VERSION 5.8 ;
BUSBITCHARS "[]" ;
DIVIDERCHAR "/" ;
UNITS
    DATABASE MICRONS 1000 ;
END UNITS

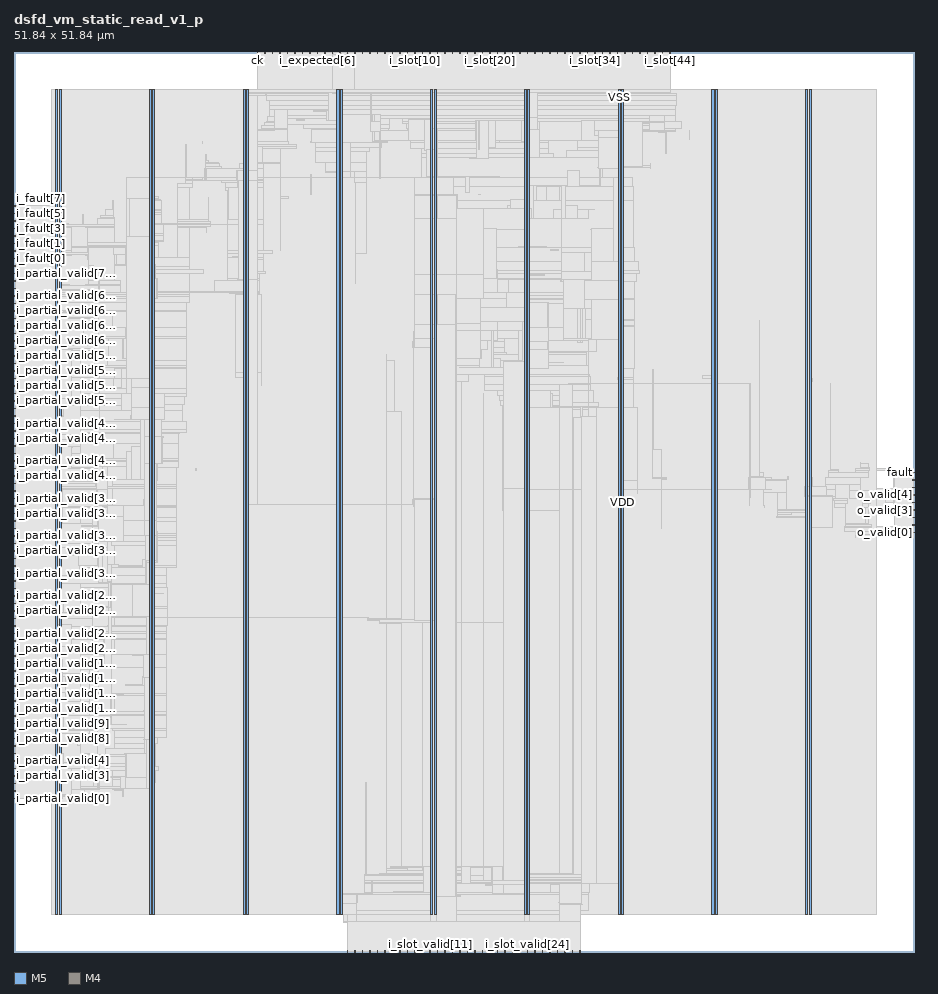
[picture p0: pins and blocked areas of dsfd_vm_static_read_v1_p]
MACRO dsfd_vm_static_read_v1_p
  FOREIGN dsfd_vm_static_read_v1_p 0 0 ;
  CLASS BLOCK ;
  SIZE 51.84 BY 51.84 ;
  PIN ck
    DIRECTION INPUT ;
    USE SIGNAL ;
    PORT
      LAYER M5 ;
        RECT  14.016 51.756 14.04 51.84 ;
    END
  END ck
  PIN fault
    DIRECTION OUTPUT ;
    USE SIGNAL ;
    PORT
      LAYER M4 ;
        RECT  51.756 27.6 51.84 27.624 ;
    END
  END fault
  PIN i_expected[0]
    DIRECTION INPUT ;
    USE SIGNAL ;
    PORT
      LAYER M5 ;
        RECT  14.88 51.756 14.904 51.84 ;
    END
  END i_expected[0]
  PIN i_expected[1]
    DIRECTION INPUT ;
    USE SIGNAL ;
    PORT
      LAYER M5 ;
        RECT  15.312 51.756 15.336 51.84 ;
    END
  END i_expected[1]
  PIN i_expected[2]
    DIRECTION INPUT ;
    USE SIGNAL ;
    PORT
      LAYER M5 ;
        RECT  15.744 51.756 15.768 51.84 ;
    END
  END i_expected[2]
  PIN i_expected[3]
    DIRECTION INPUT ;
    USE SIGNAL ;
    PORT
      LAYER M5 ;
        RECT  16.176 51.756 16.2 51.84 ;
    END
  END i_expected[3]
  PIN i_expected[4]
    DIRECTION INPUT ;
    USE SIGNAL ;
    PORT
      LAYER M5 ;
        RECT  16.608 51.756 16.632 51.84 ;
    END
  END i_expected[4]
  PIN i_expected[5]
    DIRECTION INPUT ;
    USE SIGNAL ;
    PORT
      LAYER M5 ;
        RECT  17.04 51.756 17.064 51.84 ;
    END
  END i_expected[5]
  PIN i_expected[6]
    DIRECTION INPUT ;
    USE SIGNAL ;
    PORT
      LAYER M5 ;
        RECT  17.472 51.756 17.496 51.84 ;
    END
  END i_expected[6]
  PIN i_expected[7]
    DIRECTION INPUT ;
    USE SIGNAL ;
    PORT
      LAYER M5 ;
        RECT  17.904 51.756 17.928 51.84 ;
    END
  END i_expected[7]
  PIN i_expected[8]
    DIRECTION INPUT ;
    USE SIGNAL ;
    PORT
      LAYER M5 ;
        RECT  18.336 51.756 18.36 51.84 ;
    END
  END i_expected[8]
  PIN i_fault[0]
    DIRECTION INPUT ;
    USE SIGNAL ;
    PORT
      LAYER M4 ;
        RECT  0 39.936 0.084 39.96 ;
    END
  END i_fault[0]
  PIN i_fault[1]
    DIRECTION INPUT ;
    USE SIGNAL ;
    PORT
      LAYER M4 ;
        RECT  0 40.368 0.084 40.392 ;
    END
  END i_fault[1]
  PIN i_fault[2]
    DIRECTION INPUT ;
    USE SIGNAL ;
    PORT
      LAYER M4 ;
        RECT  0 40.8 0.084 40.824 ;
    END
  END i_fault[2]
  PIN i_fault[3]
    DIRECTION INPUT ;
    USE SIGNAL ;
    PORT
      LAYER M4 ;
        RECT  0 41.232 0.084 41.256 ;
    END
  END i_fault[3]
  PIN i_fault[4]
    DIRECTION INPUT ;
    USE SIGNAL ;
    PORT
      LAYER M4 ;
        RECT  0 41.664 0.084 41.688 ;
    END
  END i_fault[4]
  PIN i_fault[5]
    DIRECTION INPUT ;
    USE SIGNAL ;
    PORT
      LAYER M4 ;
        RECT  0 42.096 0.084 42.12 ;
    END
  END i_fault[5]
  PIN i_fault[6]
    DIRECTION INPUT ;
    USE SIGNAL ;
    PORT
      LAYER M4 ;
        RECT  0 42.528 0.084 42.552 ;
    END
  END i_fault[6]
  PIN i_fault[7]
    DIRECTION INPUT ;
    USE SIGNAL ;
    PORT
      LAYER M4 ;
        RECT  0 42.96 0.084 42.984 ;
    END
  END i_fault[7]
  PIN i_partial_valid[0]
    DIRECTION INPUT ;
    USE SIGNAL ;
    PORT
      LAYER M4 ;
        RECT  0 8.832 0.084 8.856 ;
    END
  END i_partial_valid[0]
  PIN i_partial_valid[10]
    DIRECTION INPUT ;
    USE SIGNAL ;
    PORT
      LAYER M4 ;
        RECT  0 13.152 0.084 13.176 ;
    END
  END i_partial_valid[10]
  PIN i_partial_valid[11]
    DIRECTION INPUT ;
    USE SIGNAL ;
    PORT
      LAYER M4 ;
        RECT  0 13.584 0.084 13.608 ;
    END
  END i_partial_valid[11]
  PIN i_partial_valid[12]
    DIRECTION INPUT ;
    USE SIGNAL ;
    PORT
      LAYER M4 ;
        RECT  0 14.016 0.084 14.04 ;
    END
  END i_partial_valid[12]
  PIN i_partial_valid[13]
    DIRECTION INPUT ;
    USE SIGNAL ;
    PORT
      LAYER M4 ;
        RECT  0 14.448 0.084 14.472 ;
    END
  END i_partial_valid[13]
  PIN i_partial_valid[14]
    DIRECTION INPUT ;
    USE SIGNAL ;
    PORT
      LAYER M4 ;
        RECT  0 14.88 0.084 14.904 ;
    END
  END i_partial_valid[14]
  PIN i_partial_valid[15]
    DIRECTION INPUT ;
    USE SIGNAL ;
    PORT
      LAYER M4 ;
        RECT  0 15.312 0.084 15.336 ;
    END
  END i_partial_valid[15]
  PIN i_partial_valid[16]
    DIRECTION INPUT ;
    USE SIGNAL ;
    PORT
      LAYER M4 ;
        RECT  0 15.744 0.084 15.768 ;
    END
  END i_partial_valid[16]
  PIN i_partial_valid[17]
    DIRECTION INPUT ;
    USE SIGNAL ;
    PORT
      LAYER M4 ;
        RECT  0 16.176 0.084 16.2 ;
    END
  END i_partial_valid[17]
  PIN i_partial_valid[18]
    DIRECTION INPUT ;
    USE SIGNAL ;
    PORT
      LAYER M4 ;
        RECT  0 16.608 0.084 16.632 ;
    END
  END i_partial_valid[18]
  PIN i_partial_valid[19]
    DIRECTION INPUT ;
    USE SIGNAL ;
    PORT
      LAYER M4 ;
        RECT  0 17.04 0.084 17.064 ;
    END
  END i_partial_valid[19]
  PIN i_partial_valid[1]
    DIRECTION INPUT ;
    USE SIGNAL ;
    PORT
      LAYER M4 ;
        RECT  0 9.264 0.084 9.288 ;
    END
  END i_partial_valid[1]
  PIN i_partial_valid[20]
    DIRECTION INPUT ;
    USE SIGNAL ;
    PORT
      LAYER M4 ;
        RECT  0 17.472 0.084 17.496 ;
    END
  END i_partial_valid[20]
  PIN i_partial_valid[21]
    DIRECTION INPUT ;
    USE SIGNAL ;
    PORT
      LAYER M4 ;
        RECT  0 17.904 0.084 17.928 ;
    END
  END i_partial_valid[21]
  PIN i_partial_valid[22]
    DIRECTION INPUT ;
    USE SIGNAL ;
    PORT
      LAYER M4 ;
        RECT  0 18.336 0.084 18.36 ;
    END
  END i_partial_valid[22]
  PIN i_partial_valid[23]
    DIRECTION INPUT ;
    USE SIGNAL ;
    PORT
      LAYER M4 ;
        RECT  0 18.768 0.084 18.792 ;
    END
  END i_partial_valid[23]
  PIN i_partial_valid[24]
    DIRECTION INPUT ;
    USE SIGNAL ;
    PORT
      LAYER M4 ;
        RECT  0 19.2 0.084 19.224 ;
    END
  END i_partial_valid[24]
  PIN i_partial_valid[25]
    DIRECTION INPUT ;
    USE SIGNAL ;
    PORT
      LAYER M4 ;
        RECT  0 19.632 0.084 19.656 ;
    END
  END i_partial_valid[25]
  PIN i_partial_valid[26]
    DIRECTION INPUT ;
    USE SIGNAL ;
    PORT
      LAYER M4 ;
        RECT  0 20.064 0.084 20.088 ;
    END
  END i_partial_valid[26]
  PIN i_partial_valid[27]
    DIRECTION INPUT ;
    USE SIGNAL ;
    PORT
      LAYER M4 ;
        RECT  0 20.496 0.084 20.52 ;
    END
  END i_partial_valid[27]
  PIN i_partial_valid[28]
    DIRECTION INPUT ;
    USE SIGNAL ;
    PORT
      LAYER M4 ;
        RECT  0 20.928 0.084 20.952 ;
    END
  END i_partial_valid[28]
  PIN i_partial_valid[29]
    DIRECTION INPUT ;
    USE SIGNAL ;
    PORT
      LAYER M4 ;
        RECT  0 21.36 0.084 21.384 ;
    END
  END i_partial_valid[29]
  PIN i_partial_valid[2]
    DIRECTION INPUT ;
    USE SIGNAL ;
    PORT
      LAYER M4 ;
        RECT  0 9.696 0.084 9.72 ;
    END
  END i_partial_valid[2]
  PIN i_partial_valid[30]
    DIRECTION INPUT ;
    USE SIGNAL ;
    PORT
      LAYER M4 ;
        RECT  0 21.792 0.084 21.816 ;
    END
  END i_partial_valid[30]
  PIN i_partial_valid[31]
    DIRECTION INPUT ;
    USE SIGNAL ;
    PORT
      LAYER M4 ;
        RECT  0 22.224 0.084 22.248 ;
    END
  END i_partial_valid[31]
  PIN i_partial_valid[32]
    DIRECTION INPUT ;
    USE SIGNAL ;
    PORT
      LAYER M4 ;
        RECT  0 22.656 0.084 22.68 ;
    END
  END i_partial_valid[32]
  PIN i_partial_valid[33]
    DIRECTION INPUT ;
    USE SIGNAL ;
    PORT
      LAYER M4 ;
        RECT  0 23.088 0.084 23.112 ;
    END
  END i_partial_valid[33]
  PIN i_partial_valid[34]
    DIRECTION INPUT ;
    USE SIGNAL ;
    PORT
      LAYER M4 ;
        RECT  0 23.52 0.084 23.544 ;
    END
  END i_partial_valid[34]
  PIN i_partial_valid[35]
    DIRECTION INPUT ;
    USE SIGNAL ;
    PORT
      LAYER M4 ;
        RECT  0 23.952 0.084 23.976 ;
    END
  END i_partial_valid[35]
  PIN i_partial_valid[36]
    DIRECTION INPUT ;
    USE SIGNAL ;
    PORT
      LAYER M4 ;
        RECT  0 24.384 0.084 24.408 ;
    END
  END i_partial_valid[36]
  PIN i_partial_valid[37]
    DIRECTION INPUT ;
    USE SIGNAL ;
    PORT
      LAYER M4 ;
        RECT  0 24.816 0.084 24.84 ;
    END
  END i_partial_valid[37]
  PIN i_partial_valid[38]
    DIRECTION INPUT ;
    USE SIGNAL ;
    PORT
      LAYER M4 ;
        RECT  0 25.248 0.084 25.272 ;
    END
  END i_partial_valid[38]
  PIN i_partial_valid[39]
    DIRECTION INPUT ;
    USE SIGNAL ;
    PORT
      LAYER M4 ;
        RECT  0 25.68 0.084 25.704 ;
    END
  END i_partial_valid[39]
  PIN i_partial_valid[3]
    DIRECTION INPUT ;
    USE SIGNAL ;
    PORT
      LAYER M4 ;
        RECT  0 10.128 0.084 10.152 ;
    END
  END i_partial_valid[3]
  PIN i_partial_valid[40]
    DIRECTION INPUT ;
    USE SIGNAL ;
    PORT
      LAYER M4 ;
        RECT  0 26.112 0.084 26.136 ;
    END
  END i_partial_valid[40]
  PIN i_partial_valid[41]
    DIRECTION INPUT ;
    USE SIGNAL ;
    PORT
      LAYER M4 ;
        RECT  0 26.544 0.084 26.568 ;
    END
  END i_partial_valid[41]
  PIN i_partial_valid[42]
    DIRECTION INPUT ;
    USE SIGNAL ;
    PORT
      LAYER M4 ;
        RECT  0 26.976 0.084 27 ;
    END
  END i_partial_valid[42]
  PIN i_partial_valid[43]
    DIRECTION INPUT ;
    USE SIGNAL ;
    PORT
      LAYER M4 ;
        RECT  0 27.408 0.084 27.432 ;
    END
  END i_partial_valid[43]
  PIN i_partial_valid[44]
    DIRECTION INPUT ;
    USE SIGNAL ;
    PORT
      LAYER M4 ;
        RECT  0 27.84 0.084 27.864 ;
    END
  END i_partial_valid[44]
  PIN i_partial_valid[45]
    DIRECTION INPUT ;
    USE SIGNAL ;
    PORT
      LAYER M4 ;
        RECT  0 28.272 0.084 28.296 ;
    END
  END i_partial_valid[45]
  PIN i_partial_valid[46]
    DIRECTION INPUT ;
    USE SIGNAL ;
    PORT
      LAYER M4 ;
        RECT  0 28.704 0.084 28.728 ;
    END
  END i_partial_valid[46]
  PIN i_partial_valid[47]
    DIRECTION INPUT ;
    USE SIGNAL ;
    PORT
      LAYER M4 ;
        RECT  0 29.136 0.084 29.16 ;
    END
  END i_partial_valid[47]
  PIN i_partial_valid[48]
    DIRECTION INPUT ;
    USE SIGNAL ;
    PORT
      LAYER M4 ;
        RECT  0 29.568 0.084 29.592 ;
    END
  END i_partial_valid[48]
  PIN i_partial_valid[49]
    DIRECTION INPUT ;
    USE SIGNAL ;
    PORT
      LAYER M4 ;
        RECT  0 30 0.084 30.024 ;
    END
  END i_partial_valid[49]
  PIN i_partial_valid[4]
    DIRECTION INPUT ;
    USE SIGNAL ;
    PORT
      LAYER M4 ;
        RECT  0 10.56 0.084 10.584 ;
    END
  END i_partial_valid[4]
  PIN i_partial_valid[50]
    DIRECTION INPUT ;
    USE SIGNAL ;
    PORT
      LAYER M4 ;
        RECT  0 30.432 0.084 30.456 ;
    END
  END i_partial_valid[50]
  PIN i_partial_valid[51]
    DIRECTION INPUT ;
    USE SIGNAL ;
    PORT
      LAYER M4 ;
        RECT  0 30.864 0.084 30.888 ;
    END
  END i_partial_valid[51]
  PIN i_partial_valid[52]
    DIRECTION INPUT ;
    USE SIGNAL ;
    PORT
      LAYER M4 ;
        RECT  0 31.296 0.084 31.32 ;
    END
  END i_partial_valid[52]
  PIN i_partial_valid[53]
    DIRECTION INPUT ;
    USE SIGNAL ;
    PORT
      LAYER M4 ;
        RECT  0 31.728 0.084 31.752 ;
    END
  END i_partial_valid[53]
  PIN i_partial_valid[54]
    DIRECTION INPUT ;
    USE SIGNAL ;
    PORT
      LAYER M4 ;
        RECT  0 32.16 0.084 32.184 ;
    END
  END i_partial_valid[54]
  PIN i_partial_valid[55]
    DIRECTION INPUT ;
    USE SIGNAL ;
    PORT
      LAYER M4 ;
        RECT  0 32.592 0.084 32.616 ;
    END
  END i_partial_valid[55]
  PIN i_partial_valid[56]
    DIRECTION INPUT ;
    USE SIGNAL ;
    PORT
      LAYER M4 ;
        RECT  0 33.024 0.084 33.048 ;
    END
  END i_partial_valid[56]
  PIN i_partial_valid[57]
    DIRECTION INPUT ;
    USE SIGNAL ;
    PORT
      LAYER M4 ;
        RECT  0 33.456 0.084 33.48 ;
    END
  END i_partial_valid[57]
  PIN i_partial_valid[58]
    DIRECTION INPUT ;
    USE SIGNAL ;
    PORT
      LAYER M4 ;
        RECT  0 33.888 0.084 33.912 ;
    END
  END i_partial_valid[58]
  PIN i_partial_valid[59]
    DIRECTION INPUT ;
    USE SIGNAL ;
    PORT
      LAYER M4 ;
        RECT  0 34.32 0.084 34.344 ;
    END
  END i_partial_valid[59]
  PIN i_partial_valid[5]
    DIRECTION INPUT ;
    USE SIGNAL ;
    PORT
      LAYER M4 ;
        RECT  0 10.992 0.084 11.016 ;
    END
  END i_partial_valid[5]
  PIN i_partial_valid[60]
    DIRECTION INPUT ;
    USE SIGNAL ;
    PORT
      LAYER M4 ;
        RECT  0 34.752 0.084 34.776 ;
    END
  END i_partial_valid[60]
  PIN i_partial_valid[61]
    DIRECTION INPUT ;
    USE SIGNAL ;
    PORT
      LAYER M4 ;
        RECT  0 35.184 0.084 35.208 ;
    END
  END i_partial_valid[61]
  PIN i_partial_valid[62]
    DIRECTION INPUT ;
    USE SIGNAL ;
    PORT
      LAYER M4 ;
        RECT  0 35.616 0.084 35.64 ;
    END
  END i_partial_valid[62]
  PIN i_partial_valid[63]
    DIRECTION INPUT ;
    USE SIGNAL ;
    PORT
      LAYER M4 ;
        RECT  0 36.048 0.084 36.072 ;
    END
  END i_partial_valid[63]
  PIN i_partial_valid[64]
    DIRECTION INPUT ;
    USE SIGNAL ;
    PORT
      LAYER M4 ;
        RECT  0 36.48 0.084 36.504 ;
    END
  END i_partial_valid[64]
  PIN i_partial_valid[65]
    DIRECTION INPUT ;
    USE SIGNAL ;
    PORT
      LAYER M4 ;
        RECT  0 36.912 0.084 36.936 ;
    END
  END i_partial_valid[65]
  PIN i_partial_valid[66]
    DIRECTION INPUT ;
    USE SIGNAL ;
    PORT
      LAYER M4 ;
        RECT  0 37.344 0.084 37.368 ;
    END
  END i_partial_valid[66]
  PIN i_partial_valid[67]
    DIRECTION INPUT ;
    USE SIGNAL ;
    PORT
      LAYER M4 ;
        RECT  0 37.776 0.084 37.8 ;
    END
  END i_partial_valid[67]
  PIN i_partial_valid[68]
    DIRECTION INPUT ;
    USE SIGNAL ;
    PORT
      LAYER M4 ;
        RECT  0 38.208 0.084 38.232 ;
    END
  END i_partial_valid[68]
  PIN i_partial_valid[69]
    DIRECTION INPUT ;
    USE SIGNAL ;
    PORT
      LAYER M4 ;
        RECT  0 38.64 0.084 38.664 ;
    END
  END i_partial_valid[69]
  PIN i_partial_valid[6]
    DIRECTION INPUT ;
    USE SIGNAL ;
    PORT
      LAYER M4 ;
        RECT  0 11.424 0.084 11.448 ;
    END
  END i_partial_valid[6]
  PIN i_partial_valid[70]
    DIRECTION INPUT ;
    USE SIGNAL ;
    PORT
      LAYER M4 ;
        RECT  0 39.072 0.084 39.096 ;
    END
  END i_partial_valid[70]
  PIN i_partial_valid[71]
    DIRECTION INPUT ;
    USE SIGNAL ;
    PORT
      LAYER M4 ;
        RECT  0 39.504 0.084 39.528 ;
    END
  END i_partial_valid[71]
  PIN i_partial_valid[7]
    DIRECTION INPUT ;
    USE SIGNAL ;
    PORT
      LAYER M4 ;
        RECT  0 11.856 0.084 11.88 ;
    END
  END i_partial_valid[7]
  PIN i_partial_valid[8]
    DIRECTION INPUT ;
    USE SIGNAL ;
    PORT
      LAYER M4 ;
        RECT  0 12.288 0.084 12.312 ;
    END
  END i_partial_valid[8]
  PIN i_partial_valid[9]
    DIRECTION INPUT ;
    USE SIGNAL ;
    PORT
      LAYER M4 ;
        RECT  0 12.72 0.084 12.744 ;
    END
  END i_partial_valid[9]
  PIN i_slot[0]
    DIRECTION INPUT ;
    USE SIGNAL ;
    PORT
      LAYER M5 ;
        RECT  18.768 51.756 18.792 51.84 ;
    END
  END i_slot[0]
  PIN i_slot[10]
    DIRECTION INPUT ;
    USE SIGNAL ;
    PORT
      LAYER M5 ;
        RECT  23.088 51.756 23.112 51.84 ;
    END
  END i_slot[10]
  PIN i_slot[11]
    DIRECTION INPUT ;
    USE SIGNAL ;
    PORT
      LAYER M5 ;
        RECT  23.52 51.756 23.544 51.84 ;
    END
  END i_slot[11]
  PIN i_slot[12]
    DIRECTION INPUT ;
    USE SIGNAL ;
    PORT
      LAYER M5 ;
        RECT  23.952 51.756 23.976 51.84 ;
    END
  END i_slot[12]
  PIN i_slot[13]
    DIRECTION INPUT ;
    USE SIGNAL ;
    PORT
      LAYER M5 ;
        RECT  24.384 51.756 24.408 51.84 ;
    END
  END i_slot[13]
  PIN i_slot[14]
    DIRECTION INPUT ;
    USE SIGNAL ;
    PORT
      LAYER M5 ;
        RECT  24.816 51.756 24.84 51.84 ;
    END
  END i_slot[14]
  PIN i_slot[15]
    DIRECTION INPUT ;
    USE SIGNAL ;
    PORT
      LAYER M5 ;
        RECT  25.248 51.756 25.272 51.84 ;
    END
  END i_slot[15]
  PIN i_slot[16]
    DIRECTION INPUT ;
    USE SIGNAL ;
    PORT
      LAYER M5 ;
        RECT  25.68 51.756 25.704 51.84 ;
    END
  END i_slot[16]
  PIN i_slot[17]
    DIRECTION INPUT ;
    USE SIGNAL ;
    PORT
      LAYER M5 ;
        RECT  26.112 51.756 26.136 51.84 ;
    END
  END i_slot[17]
  PIN i_slot[18]
    DIRECTION INPUT ;
    USE SIGNAL ;
    PORT
      LAYER M5 ;
        RECT  26.544 51.756 26.568 51.84 ;
    END
  END i_slot[18]
  PIN i_slot[19]
    DIRECTION INPUT ;
    USE SIGNAL ;
    PORT
      LAYER M5 ;
        RECT  26.976 51.756 27 51.84 ;
    END
  END i_slot[19]
  PIN i_slot[1]
    DIRECTION INPUT ;
    USE SIGNAL ;
    PORT
      LAYER M5 ;
        RECT  19.2 51.756 19.224 51.84 ;
    END
  END i_slot[1]
  PIN i_slot[20]
    DIRECTION INPUT ;
    USE SIGNAL ;
    PORT
      LAYER M5 ;
        RECT  27.408 51.756 27.432 51.84 ;
    END
  END i_slot[20]
  PIN i_slot[21]
    DIRECTION INPUT ;
    USE SIGNAL ;
    PORT
      LAYER M5 ;
        RECT  27.84 51.756 27.864 51.84 ;
    END
  END i_slot[21]
  PIN i_slot[22]
    DIRECTION INPUT ;
    USE SIGNAL ;
    PORT
      LAYER M5 ;
        RECT  28.272 51.756 28.296 51.84 ;
    END
  END i_slot[22]
  PIN i_slot[23]
    DIRECTION INPUT ;
    USE SIGNAL ;
    PORT
      LAYER M5 ;
        RECT  28.704 51.756 28.728 51.84 ;
    END
  END i_slot[23]
  PIN i_slot[24]
    DIRECTION INPUT ;
    USE SIGNAL ;
    PORT
      LAYER M5 ;
        RECT  29.136 51.756 29.16 51.84 ;
    END
  END i_slot[24]
  PIN i_slot[25]
    DIRECTION INPUT ;
    USE SIGNAL ;
    PORT
      LAYER M5 ;
        RECT  29.568 51.756 29.592 51.84 ;
    END
  END i_slot[25]
  PIN i_slot[26]
    DIRECTION INPUT ;
    USE SIGNAL ;
    PORT
      LAYER M5 ;
        RECT  30 51.756 30.024 51.84 ;
    END
  END i_slot[26]
  PIN i_slot[27]
    DIRECTION INPUT ;
    USE SIGNAL ;
    PORT
      LAYER M5 ;
        RECT  30.432 51.756 30.456 51.84 ;
    END
  END i_slot[27]
  PIN i_slot[28]
    DIRECTION INPUT ;
    USE SIGNAL ;
    PORT
      LAYER M5 ;
        RECT  30.864 51.756 30.888 51.84 ;
    END
  END i_slot[28]
  PIN i_slot[29]
    DIRECTION INPUT ;
    USE SIGNAL ;
    PORT
      LAYER M5 ;
        RECT  31.296 51.756 31.32 51.84 ;
    END
  END i_slot[29]
  PIN i_slot[2]
    DIRECTION INPUT ;
    USE SIGNAL ;
    PORT
      LAYER M5 ;
        RECT  19.632 51.756 19.656 51.84 ;
    END
  END i_slot[2]
  PIN i_slot[30]
    DIRECTION INPUT ;
    USE SIGNAL ;
    PORT
      LAYER M5 ;
        RECT  31.728 51.756 31.752 51.84 ;
    END
  END i_slot[30]
  PIN i_slot[31]
    DIRECTION INPUT ;
    USE SIGNAL ;
    PORT
      LAYER M5 ;
        RECT  32.16 51.756 32.184 51.84 ;
    END
  END i_slot[31]
  PIN i_slot[32]
    DIRECTION INPUT ;
    USE SIGNAL ;
    PORT
      LAYER M5 ;
        RECT  32.592 51.756 32.616 51.84 ;
    END
  END i_slot[32]
  PIN i_slot[33]
    DIRECTION INPUT ;
    USE SIGNAL ;
    PORT
      LAYER M5 ;
        RECT  33.024 51.756 33.048 51.84 ;
    END
  END i_slot[33]
  PIN i_slot[34]
    DIRECTION INPUT ;
    USE SIGNAL ;
    PORT
      LAYER M5 ;
        RECT  33.456 51.756 33.48 51.84 ;
    END
  END i_slot[34]
  PIN i_slot[35]
    DIRECTION INPUT ;
    USE SIGNAL ;
    PORT
      LAYER M5 ;
        RECT  33.888 51.756 33.912 51.84 ;
    END
  END i_slot[35]
  PIN i_slot[36]
    DIRECTION INPUT ;
    USE SIGNAL ;
    PORT
      LAYER M5 ;
        RECT  34.32 51.756 34.344 51.84 ;
    END
  END i_slot[36]
  PIN i_slot[37]
    DIRECTION INPUT ;
    USE SIGNAL ;
    PORT
      LAYER M5 ;
        RECT  34.752 51.756 34.776 51.84 ;
    END
  END i_slot[37]
  PIN i_slot[38]
    DIRECTION INPUT ;
    USE SIGNAL ;
    PORT
      LAYER M5 ;
        RECT  35.184 51.756 35.208 51.84 ;
    END
  END i_slot[38]
  PIN i_slot[39]
    DIRECTION INPUT ;
    USE SIGNAL ;
    PORT
      LAYER M5 ;
        RECT  35.616 51.756 35.64 51.84 ;
    END
  END i_slot[39]
  PIN i_slot[3]
    DIRECTION INPUT ;
    USE SIGNAL ;
    PORT
      LAYER M5 ;
        RECT  20.064 51.756 20.088 51.84 ;
    END
  END i_slot[3]
  PIN i_slot[40]
    DIRECTION INPUT ;
    USE SIGNAL ;
    PORT
      LAYER M5 ;
        RECT  36.048 51.756 36.072 51.84 ;
    END
  END i_slot[40]
  PIN i_slot[41]
    DIRECTION INPUT ;
    USE SIGNAL ;
    PORT
      LAYER M5 ;
        RECT  36.48 51.756 36.504 51.84 ;
    END
  END i_slot[41]
  PIN i_slot[42]
    DIRECTION INPUT ;
    USE SIGNAL ;
    PORT
      LAYER M5 ;
        RECT  36.912 51.756 36.936 51.84 ;
    END
  END i_slot[42]
  PIN i_slot[43]
    DIRECTION INPUT ;
    USE SIGNAL ;
    PORT
      LAYER M5 ;
        RECT  37.344 51.756 37.368 51.84 ;
    END
  END i_slot[43]
  PIN i_slot[44]
    DIRECTION INPUT ;
    USE SIGNAL ;
    PORT
      LAYER M5 ;
        RECT  37.776 51.756 37.8 51.84 ;
    END
  END i_slot[44]
  PIN i_slot[4]
    DIRECTION INPUT ;
    USE SIGNAL ;
    PORT
      LAYER M5 ;
        RECT  20.496 51.756 20.52 51.84 ;
    END
  END i_slot[4]
  PIN i_slot[5]
    DIRECTION INPUT ;
    USE SIGNAL ;
    PORT
      LAYER M5 ;
        RECT  20.928 51.756 20.952 51.84 ;
    END
  END i_slot[5]
  PIN i_slot[6]
    DIRECTION INPUT ;
    USE SIGNAL ;
    PORT
      LAYER M5 ;
        RECT  21.36 51.756 21.384 51.84 ;
    END
  END i_slot[6]
  PIN i_slot[7]
    DIRECTION INPUT ;
    USE SIGNAL ;
    PORT
      LAYER M5 ;
        RECT  21.792 51.756 21.816 51.84 ;
    END
  END i_slot[7]
  PIN i_slot[8]
    DIRECTION INPUT ;
    USE SIGNAL ;
    PORT
      LAYER M5 ;
        RECT  22.224 51.756 22.248 51.84 ;
    END
  END i_slot[8]
  PIN i_slot[9]
    DIRECTION INPUT ;
    USE SIGNAL ;
    PORT
      LAYER M5 ;
        RECT  22.656 51.756 22.68 51.84 ;
    END
  END i_slot[9]
  PIN i_slot_valid[0]
    DIRECTION INPUT ;
    USE SIGNAL ;
    PORT
      LAYER M5 ;
        RECT  19.2 0 19.224 0.084 ;
    END
  END i_slot_valid[0]
  PIN i_slot_valid[10]
    DIRECTION INPUT ;
    USE SIGNAL ;
    PORT
      LAYER M5 ;
        RECT  23.52 0 23.544 0.084 ;
    END
  END i_slot_valid[10]
  PIN i_slot_valid[11]
    DIRECTION INPUT ;
    USE SIGNAL ;
    PORT
      LAYER M5 ;
        RECT  23.952 0 23.976 0.084 ;
    END
  END i_slot_valid[11]
  PIN i_slot_valid[12]
    DIRECTION INPUT ;
    USE SIGNAL ;
    PORT
      LAYER M5 ;
        RECT  24.384 0 24.408 0.084 ;
    END
  END i_slot_valid[12]
  PIN i_slot_valid[13]
    DIRECTION INPUT ;
    USE SIGNAL ;
    PORT
      LAYER M5 ;
        RECT  24.816 0 24.84 0.084 ;
    END
  END i_slot_valid[13]
  PIN i_slot_valid[14]
    DIRECTION INPUT ;
    USE SIGNAL ;
    PORT
      LAYER M5 ;
        RECT  25.248 0 25.272 0.084 ;
    END
  END i_slot_valid[14]
  PIN i_slot_valid[15]
    DIRECTION INPUT ;
    USE SIGNAL ;
    PORT
      LAYER M5 ;
        RECT  25.68 0 25.704 0.084 ;
    END
  END i_slot_valid[15]
  PIN i_slot_valid[16]
    DIRECTION INPUT ;
    USE SIGNAL ;
    PORT
      LAYER M5 ;
        RECT  26.112 0 26.136 0.084 ;
    END
  END i_slot_valid[16]
  PIN i_slot_valid[17]
    DIRECTION INPUT ;
    USE SIGNAL ;
    PORT
      LAYER M5 ;
        RECT  26.544 0 26.568 0.084 ;
    END
  END i_slot_valid[17]
  PIN i_slot_valid[18]
    DIRECTION INPUT ;
    USE SIGNAL ;
    PORT
      LAYER M5 ;
        RECT  26.976 0 27 0.084 ;
    END
  END i_slot_valid[18]
  PIN i_slot_valid[19]
    DIRECTION INPUT ;
    USE SIGNAL ;
    PORT
      LAYER M5 ;
        RECT  27.408 0 27.432 0.084 ;
    END
  END i_slot_valid[19]
  PIN i_slot_valid[1]
    DIRECTION INPUT ;
    USE SIGNAL ;
    PORT
      LAYER M5 ;
        RECT  19.632 0 19.656 0.084 ;
    END
  END i_slot_valid[1]
  PIN i_slot_valid[20]
    DIRECTION INPUT ;
    USE SIGNAL ;
    PORT
      LAYER M5 ;
        RECT  27.84 0 27.864 0.084 ;
    END
  END i_slot_valid[20]
  PIN i_slot_valid[21]
    DIRECTION INPUT ;
    USE SIGNAL ;
    PORT
      LAYER M5 ;
        RECT  28.272 0 28.296 0.084 ;
    END
  END i_slot_valid[21]
  PIN i_slot_valid[22]
    DIRECTION INPUT ;
    USE SIGNAL ;
    PORT
      LAYER M5 ;
        RECT  28.704 0 28.728 0.084 ;
    END
  END i_slot_valid[22]
  PIN i_slot_valid[23]
    DIRECTION INPUT ;
    USE SIGNAL ;
    PORT
      LAYER M5 ;
        RECT  29.136 0 29.16 0.084 ;
    END
  END i_slot_valid[23]
  PIN i_slot_valid[24]
    DIRECTION INPUT ;
    USE SIGNAL ;
    PORT
      LAYER M5 ;
        RECT  29.568 0 29.592 0.084 ;
    END
  END i_slot_valid[24]
  PIN i_slot_valid[25]
    DIRECTION INPUT ;
    USE SIGNAL ;
    PORT
      LAYER M5 ;
        RECT  30 0 30.024 0.084 ;
    END
  END i_slot_valid[25]
  PIN i_slot_valid[26]
    DIRECTION INPUT ;
    USE SIGNAL ;
    PORT
      LAYER M5 ;
        RECT  30.432 0 30.456 0.084 ;
    END
  END i_slot_valid[26]
  PIN i_slot_valid[27]
    DIRECTION INPUT ;
    USE SIGNAL ;
    PORT
      LAYER M5 ;
        RECT  30.864 0 30.888 0.084 ;
    END
  END i_slot_valid[27]
  PIN i_slot_valid[28]
    DIRECTION INPUT ;
    USE SIGNAL ;
    PORT
      LAYER M5 ;
        RECT  31.296 0 31.32 0.084 ;
    END
  END i_slot_valid[28]
  PIN i_slot_valid[29]
    DIRECTION INPUT ;
    USE SIGNAL ;
    PORT
      LAYER M5 ;
        RECT  31.728 0 31.752 0.084 ;
    END
  END i_slot_valid[29]
  PIN i_slot_valid[2]
    DIRECTION INPUT ;
    USE SIGNAL ;
    PORT
      LAYER M5 ;
        RECT  20.064 0 20.088 0.084 ;
    END
  END i_slot_valid[2]
  PIN i_slot_valid[30]
    DIRECTION INPUT ;
    USE SIGNAL ;
    PORT
      LAYER M5 ;
        RECT  32.16 0 32.184 0.084 ;
    END
  END i_slot_valid[30]
  PIN i_slot_valid[31]
    DIRECTION INPUT ;
    USE SIGNAL ;
    PORT
      LAYER M5 ;
        RECT  32.592 0 32.616 0.084 ;
    END
  END i_slot_valid[31]
  PIN i_slot_valid[3]
    DIRECTION INPUT ;
    USE SIGNAL ;
    PORT
      LAYER M5 ;
        RECT  20.496 0 20.52 0.084 ;
    END
  END i_slot_valid[3]
  PIN i_slot_valid[4]
    DIRECTION INPUT ;
    USE SIGNAL ;
    PORT
      LAYER M5 ;
        RECT  20.928 0 20.952 0.084 ;
    END
  END i_slot_valid[4]
  PIN i_slot_valid[5]
    DIRECTION INPUT ;
    USE SIGNAL ;
    PORT
      LAYER M5 ;
        RECT  21.36 0 21.384 0.084 ;
    END
  END i_slot_valid[5]
  PIN i_slot_valid[6]
    DIRECTION INPUT ;
    USE SIGNAL ;
    PORT
      LAYER M5 ;
        RECT  21.792 0 21.816 0.084 ;
    END
  END i_slot_valid[6]
  PIN i_slot_valid[7]
    DIRECTION INPUT ;
    USE SIGNAL ;
    PORT
      LAYER M5 ;
        RECT  22.224 0 22.248 0.084 ;
    END
  END i_slot_valid[7]
  PIN i_slot_valid[8]
    DIRECTION INPUT ;
    USE SIGNAL ;
    PORT
      LAYER M5 ;
        RECT  22.656 0 22.68 0.084 ;
    END
  END i_slot_valid[8]
  PIN i_slot_valid[9]
    DIRECTION INPUT ;
    USE SIGNAL ;
    PORT
      LAYER M5 ;
        RECT  23.088 0 23.112 0.084 ;
    END
  END i_slot_valid[9]
  PIN o_valid[0]
    DIRECTION OUTPUT ;
    USE SIGNAL ;
    PORT
      LAYER M4 ;
        RECT  51.756 24.144 51.84 24.168 ;
    END
  END o_valid[0]
  PIN o_valid[1]
    DIRECTION OUTPUT ;
    USE SIGNAL ;
    PORT
      LAYER M4 ;
        RECT  51.756 24.576 51.84 24.6 ;
    END
  END o_valid[1]
  PIN o_valid[2]
    DIRECTION OUTPUT ;
    USE SIGNAL ;
    PORT
      LAYER M4 ;
        RECT  51.756 25.008 51.84 25.032 ;
    END
  END o_valid[2]
  PIN o_valid[3]
    DIRECTION OUTPUT ;
    USE SIGNAL ;
    PORT
      LAYER M4 ;
        RECT  51.756 25.44 51.84 25.464 ;
    END
  END o_valid[3]
  PIN o_valid[4]
    DIRECTION OUTPUT ;
    USE SIGNAL ;
    PORT
      LAYER M4 ;
        RECT  51.756 25.872 51.84 25.896 ;
    END
  END o_valid[4]
  PIN o_valid[5]
    DIRECTION OUTPUT ;
    USE SIGNAL ;
    PORT
      LAYER M4 ;
        RECT  51.756 26.304 51.84 26.328 ;
    END
  END o_valid[5]
  PIN o_valid[6]
    DIRECTION OUTPUT ;
    USE SIGNAL ;
    PORT
      LAYER M4 ;
        RECT  51.756 26.736 51.84 26.76 ;
    END
  END o_valid[6]
  PIN o_valid[7]
    DIRECTION OUTPUT ;
    USE SIGNAL ;
    PORT
      LAYER M4 ;
        RECT  51.756 27.168 51.84 27.192 ;
    END
  END o_valid[7]
  PIN rst_n
    DIRECTION INPUT ;
    USE SIGNAL ;
    PORT
      LAYER M5 ;
        RECT  14.448 51.756 14.472 51.84 ;
    END
  END rst_n
  PIN VDD
    DIRECTION INOUT ;
    USE POWER ;
    PORT
      LAYER M5 ;
        RECT  45.792 2.151 45.912 49.689 ;
        RECT  40.392 2.151 40.512 49.689 ;
        RECT  34.992 2.151 35.112 49.689 ;
        RECT  29.592 2.151 29.712 49.689 ;
        RECT  24.192 2.151 24.312 49.689 ;
        RECT  18.792 2.151 18.912 49.689 ;
        RECT  13.392 2.151 13.512 49.689 ;
        RECT  7.992 2.151 8.112 49.689 ;
        RECT  2.592 2.151 2.712 49.689 ;
    END
  END VDD
  PIN VSS
    DIRECTION INOUT ;
    USE GROUND ;
    PORT
      LAYER M5 ;
        RECT  45.6 2.137 45.72 49.703 ;
        RECT  40.2 2.137 40.32 49.703 ;
        RECT  34.8 2.137 34.92 49.703 ;
        RECT  29.4 2.137 29.52 49.703 ;
        RECT  24 2.137 24.12 49.703 ;
        RECT  18.6 2.137 18.72 49.703 ;
        RECT  13.2 2.137 13.32 49.703 ;
        RECT  7.8 2.137 7.92 49.703 ;
        RECT  2.4 2.137 2.52 49.703 ;
    END
  END VSS
  # OT_OBS_CLOSED layer=M5 d_um=1.536 added=59
  OBS
    LAYER RVTN ;
     RECT  2.16 2.16 49.68 2.295 ;
     RECT  2.16 2.565 49.68 2.835 ;
     RECT  2.16 3.105 49.68 3.375 ;
     RECT  2.16 3.645 49.68 3.915 ;
     RECT  2.16 4.185 49.68 4.455 ;
     RECT  2.16 4.725 49.68 4.995 ;
     RECT  2.16 5.265 49.68 5.535 ;
     RECT  2.16 5.805 49.68 6.075 ;
     RECT  2.16 6.345 49.68 6.615 ;
     RECT  2.16 6.885 49.68 7.155 ;
     RECT  2.16 7.425 49.68 7.695 ;
     RECT  2.16 7.965 49.68 8.235 ;
     RECT  2.16 8.505 49.68 8.775 ;
     RECT  2.16 9.045 49.68 9.315 ;
     RECT  2.16 9.585 49.68 9.855 ;
     RECT  2.16 10.125 49.68 10.395 ;
     RECT  2.16 10.665 49.68 10.935 ;
     RECT  2.16 11.205 49.68 11.475 ;
     RECT  2.16 11.745 49.68 12.015 ;
     RECT  2.16 12.285 49.68 12.555 ;
     RECT  2.16 12.825 49.68 13.095 ;
     RECT  2.16 13.365 49.68 13.635 ;
     RECT  2.16 13.905 49.68 14.175 ;
     RECT  2.16 14.445 49.68 14.715 ;
     RECT  2.16 14.985 49.68 15.255 ;
     RECT  2.16 15.525 49.68 15.795 ;
     RECT  2.16 16.065 49.68 16.335 ;
     RECT  2.16 16.605 49.68 16.875 ;
     RECT  2.16 17.145 49.68 17.415 ;
     RECT  2.16 17.685 49.68 17.955 ;
     RECT  2.16 18.225 49.68 18.495 ;
     RECT  2.16 18.765 49.68 19.035 ;
     RECT  2.16 19.305 49.68 19.575 ;
     RECT  2.16 19.845 49.68 20.115 ;
     RECT  2.16 20.385 49.68 20.655 ;
     RECT  2.16 20.925 49.68 21.195 ;
     RECT  2.16 21.465 49.68 21.735 ;
     RECT  2.16 22.005 49.68 22.275 ;
     RECT  2.16 22.545 49.68 22.815 ;
     RECT  2.16 23.085 49.68 23.355 ;
     RECT  2.16 23.625 49.68 23.895 ;
     RECT  2.16 24.165 49.68 24.435 ;
     RECT  2.16 24.705 49.68 24.975 ;
     RECT  2.16 25.245 49.68 25.515 ;
     RECT  2.16 25.785 49.68 26.055 ;
     RECT  2.16 26.325 49.68 26.595 ;
     RECT  2.16 26.865 49.68 27.135 ;
     RECT  2.16 27.405 49.68 27.675 ;
     RECT  2.16 27.945 49.68 28.215 ;
     RECT  2.16 28.485 49.68 28.755 ;
     RECT  2.16 29.025 49.68 29.295 ;
     RECT  2.16 29.565 49.68 29.835 ;
     RECT  2.16 30.105 49.68 30.375 ;
     RECT  2.16 30.645 49.68 30.915 ;
     RECT  2.16 31.185 49.68 31.455 ;
     RECT  2.16 31.725 49.68 31.995 ;
     RECT  2.16 32.265 49.68 32.535 ;
     RECT  2.16 32.805 49.68 33.075 ;
     RECT  2.16 33.345 49.68 33.615 ;
     RECT  2.16 33.885 49.68 34.155 ;
     RECT  2.16 34.425 49.68 34.695 ;
     RECT  2.16 34.965 49.68 35.235 ;
     RECT  2.16 35.505 49.68 35.775 ;
     RECT  2.16 36.045 49.68 36.315 ;
     RECT  2.16 36.585 49.68 36.855 ;
     RECT  2.16 37.125 49.68 37.395 ;
     RECT  2.16 37.665 49.68 37.935 ;
     RECT  2.16 38.205 49.68 38.475 ;
     RECT  2.16 38.745 49.68 39.015 ;
     RECT  2.16 39.285 49.68 39.555 ;
     RECT  2.16 39.825 49.68 40.095 ;
     RECT  2.16 40.365 49.68 40.635 ;
     RECT  2.16 40.905 49.68 41.175 ;
     RECT  2.16 41.445 49.68 41.715 ;
     RECT  2.16 41.985 49.68 42.255 ;
     RECT  2.16 42.525 49.68 42.795 ;
     RECT  2.16 43.065 49.68 43.335 ;
     RECT  2.16 43.605 49.68 43.875 ;
     RECT  2.16 44.145 49.68 44.415 ;
     RECT  2.16 44.685 49.68 44.955 ;
     RECT  2.16 45.225 49.68 45.495 ;
     RECT  2.16 45.765 49.68 46.035 ;
     RECT  2.16 46.305 49.68 46.575 ;
     RECT  2.16 46.845 49.68 47.115 ;
     RECT  2.16 47.385 49.68 47.655 ;
     RECT  2.16 47.925 49.68 48.195 ;
     RECT  2.16 48.465 49.68 48.735 ;
     RECT  2.16 49.005 49.68 49.275 ;
     RECT  2.16 49.545 49.68 49.68 ;
    LAYER RVTP ;
     RECT  2.16 2.295 49.68 2.565 ;
     RECT  2.16 2.835 49.68 3.105 ;
     RECT  2.16 3.375 49.68 3.645 ;
     RECT  2.16 3.915 49.68 4.185 ;
     RECT  2.16 4.455 49.68 4.725 ;
     RECT  2.16 4.995 49.68 5.265 ;
     RECT  2.16 5.535 49.68 5.805 ;
     RECT  2.16 6.075 49.68 6.345 ;
     RECT  2.16 6.615 49.68 6.885 ;
     RECT  2.16 7.155 49.68 7.425 ;
     RECT  2.16 7.695 49.68 7.965 ;
     RECT  2.16 8.235 49.68 8.505 ;
     RECT  2.16 8.775 49.68 9.045 ;
     RECT  2.16 9.315 49.68 9.585 ;
     RECT  2.16 9.855 49.68 10.125 ;
     RECT  2.16 10.395 49.68 10.665 ;
     RECT  2.16 10.935 49.68 11.205 ;
     RECT  2.16 11.475 49.68 11.745 ;
     RECT  2.16 12.015 49.68 12.285 ;
     RECT  2.16 12.555 49.68 12.825 ;
     RECT  2.16 13.095 49.68 13.365 ;
     RECT  2.16 13.635 49.68 13.905 ;
     RECT  2.16 14.175 49.68 14.445 ;
     RECT  2.16 14.715 49.68 14.985 ;
     RECT  2.16 15.255 49.68 15.525 ;
     RECT  2.16 15.795 49.68 16.065 ;
     RECT  2.16 16.335 49.68 16.605 ;
     RECT  2.16 16.875 49.68 17.145 ;
     RECT  2.16 17.415 49.68 17.685 ;
     RECT  2.16 17.955 49.68 18.225 ;
     RECT  2.16 18.495 49.68 18.765 ;
     RECT  2.16 19.035 49.68 19.305 ;
     RECT  2.16 19.575 49.68 19.845 ;
     RECT  2.16 20.115 49.68 20.385 ;
     RECT  2.16 20.655 49.68 20.925 ;
     RECT  2.16 21.195 49.68 21.465 ;
     RECT  2.16 21.735 49.68 22.005 ;
     RECT  2.16 22.275 49.68 22.545 ;
     RECT  2.16 22.815 49.68 23.085 ;
     RECT  2.16 23.355 49.68 23.625 ;
     RECT  2.16 23.895 49.68 24.165 ;
     RECT  2.16 24.435 49.68 24.705 ;
     RECT  2.16 24.975 49.68 25.245 ;
     RECT  2.16 25.515 49.68 25.785 ;
     RECT  2.16 26.055 49.68 26.325 ;
     RECT  2.16 26.595 49.68 26.865 ;
     RECT  2.16 27.135 49.68 27.405 ;
     RECT  2.16 27.675 49.68 27.945 ;
     RECT  2.16 28.215 49.68 28.485 ;
     RECT  2.16 28.755 49.68 29.025 ;
     RECT  2.16 29.295 49.68 29.565 ;
     RECT  2.16 29.835 49.68 30.105 ;
     RECT  2.16 30.375 49.68 30.645 ;
     RECT  2.16 30.915 49.68 31.185 ;
     RECT  2.16 31.455 49.68 31.725 ;
     RECT  2.16 31.995 49.68 32.265 ;
     RECT  2.16 32.535 49.68 32.805 ;
     RECT  2.16 33.075 49.68 33.345 ;
     RECT  2.16 33.615 49.68 33.885 ;
     RECT  2.16 34.155 49.68 34.425 ;
     RECT  2.16 34.695 49.68 34.965 ;
     RECT  2.16 35.235 49.68 35.505 ;
     RECT  2.16 35.775 49.68 36.045 ;
     RECT  2.16 36.315 49.68 36.585 ;
     RECT  2.16 36.855 49.68 37.125 ;
     RECT  2.16 37.395 49.68 37.665 ;
     RECT  2.16 37.935 49.68 38.205 ;
     RECT  2.16 38.475 49.68 38.745 ;
     RECT  2.16 39.015 49.68 39.285 ;
     RECT  2.16 39.555 49.68 39.825 ;
     RECT  2.16 40.095 49.68 40.365 ;
     RECT  2.16 40.635 49.68 40.905 ;
     RECT  2.16 41.175 49.68 41.445 ;
     RECT  2.16 41.715 49.68 41.985 ;
     RECT  2.16 42.255 49.68 42.525 ;
     RECT  2.16 42.795 49.68 43.065 ;
     RECT  2.16 43.335 49.68 43.605 ;
     RECT  2.16 43.875 49.68 44.145 ;
     RECT  2.16 44.415 49.68 44.685 ;
     RECT  2.16 44.955 49.68 45.225 ;
     RECT  2.16 45.495 49.68 45.765 ;
     RECT  2.16 46.035 49.68 46.305 ;
     RECT  2.16 46.575 49.68 46.845 ;
     RECT  2.16 47.115 49.68 47.385 ;
     RECT  2.16 47.655 49.68 47.925 ;
     RECT  2.16 48.195 49.68 48.465 ;
     RECT  2.16 48.735 49.68 49.005 ;
     RECT  2.16 49.275 49.68 49.545 ;
    LAYER M1 ;
     RECT  2.16 2.151 49.68 49.689 ;
    LAYER M2 ;
     RECT  0.535 22.212 2.16 22.23 ;
     RECT  0.535 27.342 2.16 27.36 ;
     RECT  0.103 38.178 2.16 38.196 ;
     RECT  2.16 2.151 49.68 49.689 ;
     RECT  49.68 25.326 50.207 26.694 ;
     RECT  49.68 27.756 50.675 27.864 ;
     RECT  49.68 24.138 50.711 24.498 ;
     RECT  50.207 25.866 50.711 26.694 ;
     RECT  50.675 27.756 50.711 27.774 ;
     RECT  50.711 24.336 50.747 24.498 ;
     RECT  50.747 24.336 50.783 24.354 ;
    LAYER M3 ;
     RECT  22.248 0.571 22.266 1.723 ;
     RECT  23.94 0.571 23.958 1.723 ;
     RECT  18.972 1.723 32.598 2.143 ;
     RECT  18.615 2.143 32.598 2.371 ;
     RECT  2.415 2.143 2.505 2.413 ;
     RECT  7.815 2.143 7.905 2.413 ;
     RECT  13.215 2.143 13.305 2.413 ;
     RECT  34.815 2.143 34.905 2.413 ;
     RECT  40.215 2.143 40.305 2.413 ;
     RECT  45.615 2.143 45.705 2.413 ;
     RECT  18.615 2.371 33.066 3.299 ;
     RECT  18.615 3.299 19.314 3.371 ;
     RECT  20.16 3.299 33.066 3.451 ;
     RECT  20.16 3.451 33.138 3.931 ;
     RECT  20.16 3.931 33.57 3.983 ;
     RECT  20.16 3.983 33.318 4.115 ;
     RECT  27.864 4.115 33.318 4.181 ;
     RECT  28.008 4.181 33.318 4.289 ;
     RECT  20.16 4.115 27.054 4.415 ;
     RECT  20.16 4.415 25.758 4.451 ;
     RECT  20.268 4.451 25.758 4.487 ;
     RECT  28.26 4.289 33.318 4.487 ;
     RECT  21.024 4.487 25.758 4.523 ;
     RECT  28.26 4.487 32.202 4.523 ;
     RECT  32.94 4.487 33.318 4.649 ;
     RECT  21.456 4.523 25.758 4.721 ;
     RECT  21.456 4.721 22.662 4.829 ;
     RECT  2.415 2.413 2.697 8.851 ;
     RECT  2.415 8.851 2.79 8.977 ;
     RECT  2.415 8.977 3.294 9.013 ;
     RECT  4.068 8.977 4.086 9.013 ;
     RECT  6.264 8.941 6.282 9.319 ;
     RECT  5.796 9.319 6.282 9.355 ;
     RECT  2.415 9.013 4.086 9.383 ;
     RECT  3.816 9.383 4.086 9.391 ;
     RECT  4.824 9.349 4.842 9.391 ;
     RECT  5.688 9.355 6.282 9.391 ;
     RECT  3.816 9.391 6.282 9.509 ;
     RECT  2.415 9.383 2.79 9.691 ;
     RECT  20.268 4.487 20.286 9.779 ;
     RECT  7.815 2.413 8.097 9.787 ;
     RECT  2.304 9.691 2.79 9.815 ;
     RECT  5.688 9.509 6.282 9.931 ;
     RECT  7.815 9.787 8.154 9.931 ;
     RECT  2.415 9.815 2.79 10.123 ;
     RECT  3.816 9.509 4.554 10.355 ;
     RECT  5.688 9.931 8.154 10.471 ;
     RECT  2.415 10.123 2.97 10.555 ;
     RECT  3.816 10.355 4.086 10.555 ;
     RECT  5.364 10.471 8.298 10.661 ;
     RECT  5.364 10.661 8.154 10.843 ;
     RECT  2.304 10.555 4.086 10.895 ;
     RECT  3.816 10.895 4.086 11.281 ;
     RECT  4.824 10.843 8.154 11.281 ;
     RECT  3.816 11.281 8.154 11.399 ;
     RECT  3.816 11.399 4.374 11.435 ;
     RECT  2.304 10.895 2.826 11.453 ;
     RECT  5.256 11.399 8.154 11.705 ;
     RECT  3.816 11.435 3.834 11.911 ;
     RECT  5.796 11.705 8.154 12.019 ;
     RECT  5.796 12.019 8.262 12.361 ;
     RECT  3.636 11.911 3.834 12.451 ;
     RECT  2.304 11.453 2.697 12.595 ;
     RECT  3.636 12.451 4.338 12.595 ;
     RECT  2.304 12.595 4.338 12.757 ;
     RECT  5.796 12.361 8.766 12.757 ;
     RECT  2.304 12.757 4.842 12.901 ;
     RECT  5.652 12.757 8.766 12.901 ;
     RECT  2.304 12.901 8.766 13.595 ;
     RECT  5.544 13.595 8.766 13.661 ;
     RECT  5.688 13.661 8.766 13.865 ;
     RECT  2.304 13.595 4.338 14.405 ;
     RECT  2.304 14.405 3.042 14.513 ;
     RECT  2.412 14.513 3.042 14.639 ;
     RECT  5.796 13.865 8.766 14.755 ;
     RECT  3.816 14.405 4.338 14.779 ;
     RECT  3.816 14.779 4.878 14.791 ;
     RECT  5.688 14.755 8.766 14.791 ;
     RECT  3.816 14.791 8.766 14.909 ;
     RECT  2.412 14.639 2.97 14.945 ;
     RECT  3.816 14.909 4.374 14.945 ;
     RECT  2.415 14.945 2.97 15.727 ;
     RECT  2.304 15.727 2.97 15.829 ;
     RECT  3.816 14.945 4.338 15.829 ;
     RECT  2.304 15.829 4.338 16.025 ;
     RECT  3.816 16.025 4.338 16.267 ;
     RECT  2.304 16.025 2.79 16.295 ;
     RECT  3.816 16.267 4.842 16.411 ;
     RECT  5.58 14.909 8.766 16.411 ;
     RECT  2.415 16.295 2.79 16.835 ;
     RECT  2.415 16.835 2.697 17.035 ;
     RECT  2.304 17.035 2.697 17.105 ;
     RECT  3.816 16.411 8.766 17.117 ;
     RECT  2.415 17.105 2.697 17.611 ;
     RECT  3.816 17.117 4.518 17.611 ;
     RECT  2.415 17.611 4.518 17.989 ;
     RECT  5.796 17.117 8.766 17.995 ;
     RECT  2.415 17.989 4.842 18.031 ;
     RECT  5.688 17.995 8.766 18.031 ;
     RECT  2.415 18.031 8.766 18.331 ;
     RECT  2.304 18.331 8.766 18.455 ;
     RECT  2.415 18.455 8.766 18.725 ;
     RECT  5.436 18.725 8.766 18.797 ;
     RECT  5.796 18.797 8.766 18.805 ;
     RECT  21.456 4.829 22.338 18.931 ;
     RECT  21.06 18.931 22.338 19.099 ;
     RECT  2.415 18.725 4.518 19.195 ;
     RECT  20.376 19.099 22.338 19.229 ;
     RECT  20.376 19.229 20.394 19.277 ;
     RECT  2.304 19.195 4.518 19.535 ;
     RECT  5.796 18.805 8.838 19.777 ;
     RECT  3.816 19.535 4.518 19.819 ;
     RECT  3.816 19.819 4.878 19.921 ;
     RECT  5.652 19.777 8.838 19.921 ;
     RECT  2.304 19.535 2.826 20.093 ;
     RECT  3.816 19.921 8.838 20.993 ;
     RECT  2.304 20.093 2.697 21.211 ;
     RECT  3.816 20.993 8.766 21.211 ;
     RECT  2.304 21.211 8.766 21.695 ;
     RECT  3.744 21.695 8.766 22.171 ;
     RECT  3.744 22.171 9.342 22.235 ;
     RECT  0.54 22.207 0.558 22.253 ;
     RECT  5.364 22.235 9.342 22.271 ;
     RECT  2.304 21.695 2.697 22.843 ;
     RECT  3.744 22.235 4.554 22.843 ;
     RECT  2.304 22.843 4.554 23.317 ;
     RECT  5.796 22.271 9.342 23.395 ;
     RECT  2.304 23.317 4.842 23.549 ;
     RECT  5.616 23.395 9.342 23.701 ;
     RECT  5.256 23.701 9.342 23.855 ;
     RECT  5.724 23.855 9.342 23.971 ;
     RECT  48.456 23.899 48.474 23.971 ;
     RECT  48.456 23.971 48.654 24.061 ;
     RECT  5.724 23.971 9.378 24.089 ;
     RECT  50.688 24.133 50.706 24.173 ;
     RECT  48.456 24.061 49.338 24.205 ;
     RECT  45.615 2.413 45.897 24.475 ;
     RECT  47.808 24.205 49.338 24.475 ;
     RECT  47.808 24.475 49.374 24.503 ;
     RECT  47.052 24.439 47.07 24.509 ;
     RECT  45.576 24.475 45.897 24.511 ;
     RECT  47.88 24.503 49.374 24.629 ;
     RECT  2.304 23.549 4.518 24.665 ;
     RECT  47.88 24.629 49.194 24.701 ;
     RECT  5.724 24.089 9.342 24.781 ;
     RECT  45.576 24.511 46.53 24.809 ;
     RECT  2.304 24.665 2.79 24.935 ;
     RECT  5.652 24.781 9.342 25.015 ;
     RECT  50.724 24.331 50.778 25.037 ;
     RECT  3.816 24.665 4.518 25.045 ;
     RECT  3.816 25.045 4.878 25.051 ;
     RECT  5.616 25.015 9.342 25.051 ;
     RECT  43.956 25.051 43.974 25.213 ;
     RECT  44.748 25.177 44.766 25.213 ;
     RECT  43.956 25.213 44.766 25.321 ;
     RECT  45.576 24.809 45.954 25.321 ;
     RECT  28.26 4.523 31.446 25.411 ;
     RECT  43.956 25.321 45.954 25.439 ;
     RECT  50.184 25.321 50.202 25.469 ;
     RECT  43.956 25.439 45.897 25.475 ;
     RECT  2.415 24.935 2.79 25.591 ;
     RECT  3.816 25.051 9.342 25.591 ;
     RECT  47.88 24.701 47.898 25.591 ;
     RECT  49.068 24.701 49.194 25.591 ;
     RECT  2.415 25.591 9.342 25.675 ;
     RECT  43.2 25.591 43.218 25.744 ;
     RECT  2.304 25.675 9.342 25.745 ;
     RECT  43.164 25.744 43.218 25.745 ;
     RECT  47.268 25.591 47.898 25.825 ;
     RECT  48.888 25.591 49.194 25.825 ;
     RECT  47.268 25.825 48.006 26.011 ;
     RECT  47.16 26.011 48.006 26.123 ;
     RECT  47.16 26.123 47.322 26.131 ;
     RECT  48.888 25.825 49.338 26.131 ;
     RECT  42.372 25.717 42.39 26.237 ;
     RECT  45.615 25.475 45.897 26.251 ;
     RECT  45.54 26.251 45.897 26.257 ;
     RECT  47.016 26.131 47.322 26.257 ;
     RECT  43.164 25.745 43.182 26.491 ;
     RECT  43.956 25.475 44.514 26.491 ;
     RECT  48.132 26.131 49.338 26.591 ;
     RECT  45.54 26.257 47.322 26.627 ;
     RECT  2.412 25.745 4.518 26.629 ;
     RECT  2.412 26.629 4.806 26.671 ;
     RECT  5.652 25.745 9.342 26.671 ;
     RECT  50.688 25.861 50.706 26.765 ;
     RECT  2.412 26.671 9.342 26.789 ;
     RECT  45.54 26.627 45.99 26.789 ;
     RECT  5.652 26.789 9.342 26.905 ;
     RECT  46.764 26.627 47.322 26.905 ;
     RECT  48.132 26.591 48.762 26.905 ;
     RECT  2.412 26.789 4.698 26.971 ;
     RECT  2.304 26.971 4.698 27.095 ;
     RECT  34.815 2.413 35.097 27.175 ;
     RECT  35.892 26.401 35.91 27.175 ;
     RECT  43.164 26.491 44.514 27.175 ;
     RECT  42.516 27.175 44.514 27.203 ;
     RECT  37.296 24.403 37.314 27.211 ;
     RECT  37.296 27.211 37.602 27.301 ;
     RECT  42.516 27.203 43.65 27.307 ;
     RECT  36.792 27.301 37.602 27.329 ;
     RECT  42.372 27.307 43.65 27.329 ;
     RECT  45.615 26.789 45.99 27.329 ;
     RECT  46.764 26.905 48.762 27.329 ;
     RECT  46.908 27.329 48.762 27.337 ;
     RECT  42.372 27.329 43.29 27.341 ;
     RECT  42.372 27.341 43.146 27.365 ;
     RECT  44.568 27.211 44.586 27.365 ;
     RECT  0.54 27.337 0.558 27.437 ;
     RECT  50.652 27.163 50.67 27.595 ;
     RECT  42.912 27.365 43.146 27.635 ;
     RECT  46.908 27.337 49.194 27.635 ;
     RECT  48.456 27.635 49.194 27.715 ;
     RECT  46.908 27.635 47.466 27.743 ;
     RECT  47.016 27.743 47.466 27.779 ;
     RECT  50.652 27.595 50.706 27.779 ;
     RECT  2.415 27.095 4.698 27.835 ;
     RECT  10.476 27.751 10.494 27.869 ;
     RECT  48.456 27.715 49.302 27.869 ;
     RECT  50.652 27.779 50.67 27.869 ;
     RECT  2.304 27.835 4.698 27.905 ;
     RECT  48.744 27.869 49.302 27.905 ;
     RECT  5.652 26.905 9.378 27.913 ;
     RECT  2.415 27.905 4.698 27.931 ;
     RECT  48.744 27.905 49.194 28.139 ;
     RECT  48.744 28.139 48.762 28.175 ;
     RECT  5.652 27.913 9.486 28.255 ;
     RECT  2.415 27.931 4.734 28.291 ;
     RECT  5.58 28.255 9.486 28.291 ;
     RECT  2.415 28.291 9.486 28.409 ;
     RECT  5.652 28.409 9.486 28.445 ;
     RECT  2.415 28.409 4.446 28.481 ;
     RECT  2.415 28.481 3.834 28.687 ;
     RECT  36.792 27.329 37.314 28.949 ;
     RECT  2.412 28.687 3.834 29.131 ;
     RECT  5.724 28.445 9.486 29.299 ;
     RECT  2.304 29.131 3.834 29.497 ;
     RECT  2.304 29.497 4.158 29.795 ;
     RECT  3.816 29.795 4.158 29.875 ;
     RECT  5.112 29.299 9.486 29.875 ;
     RECT  3.816 29.875 9.522 29.911 ;
     RECT  3.816 29.911 9.954 30.101 ;
     RECT  3.816 30.101 9.918 30.569 ;
     RECT  32.184 4.523 32.202 30.811 ;
     RECT  33.3 4.649 33.318 30.811 ;
     RECT  2.304 29.795 2.697 30.847 ;
     RECT  21.456 19.229 22.338 31.109 ;
     RECT  3.816 30.569 9.702 31.181 ;
     RECT  32.184 30.811 33.318 31.261 ;
     RECT  32.184 31.261 33.39 31.339 ;
     RECT  34.815 27.175 35.91 31.379 ;
     RECT  32.184 31.339 33.426 31.387 ;
     RECT  2.304 30.847 2.826 31.415 ;
     RECT  28.116 25.411 31.446 31.459 ;
     RECT  2.415 31.415 2.826 31.495 ;
     RECT  3.816 31.181 6.21 31.495 ;
     RECT  6.948 31.181 9.702 31.531 ;
     RECT  32.184 31.387 33.642 31.649 ;
     RECT  28.044 31.459 31.446 31.765 ;
     RECT  2.415 31.495 6.21 31.901 ;
     RECT  6.948 31.531 9.846 31.999 ;
     RECT  27.936 31.765 31.446 32.035 ;
     RECT  3.816 31.901 6.21 32.155 ;
     RECT  6.948 31.999 9.918 32.155 ;
     RECT  27.036 4.415 27.054 32.189 ;
     RECT  32.184 31.649 33.39 32.333 ;
     RECT  27.828 32.035 31.446 32.341 ;
     RECT  3.816 32.155 9.918 32.459 ;
     RECT  3.816 32.459 6.174 32.495 ;
     RECT  27.108 32.341 31.446 32.701 ;
     RECT  32.184 32.333 33.21 32.701 ;
     RECT  47.016 27.779 47.034 32.729 ;
     RECT  23.508 4.721 25.758 32.881 ;
     RECT  45.615 27.329 45.897 32.881 ;
     RECT  34.815 31.379 35.694 32.971 ;
     RECT  2.415 31.901 2.697 33.007 ;
     RECT  40.215 2.413 40.497 33.007 ;
     RECT  45.615 32.881 45.99 33.035 ;
     RECT  2.304 33.007 2.697 33.067 ;
     RECT  3.816 32.495 4.842 33.067 ;
     RECT  34.776 32.971 35.694 33.071 ;
     RECT  13.215 2.413 13.497 33.079 ;
     RECT  27.108 32.701 33.21 33.143 ;
     RECT  39.636 33.007 40.497 33.179 ;
     RECT  27.108 33.143 33.138 33.269 ;
     RECT  23.508 32.881 26.19 33.277 ;
     RECT  27.108 33.269 33.102 33.277 ;
     RECT  2.304 33.067 4.842 33.305 ;
     RECT  12.744 33.079 13.497 33.385 ;
     RECT  14.256 32.611 14.274 33.385 ;
     RECT  36.792 28.949 36.81 33.539 ;
     RECT  2.304 33.305 2.697 33.575 ;
     RECT  5.724 32.495 6.174 33.583 ;
     RECT  6.948 32.459 9.918 33.583 ;
     RECT  34.815 33.071 35.694 33.583 ;
     RECT  5.724 33.583 9.918 33.655 ;
     RECT  3.816 33.305 4.842 33.691 ;
     RECT  5.688 33.655 9.918 33.691 ;
     RECT  3.816 33.691 9.918 33.809 ;
     RECT  23.508 33.277 33.102 33.809 ;
     RECT  5.4 33.809 9.918 34.079 ;
     RECT  21.456 31.109 21.942 34.079 ;
     RECT  2.415 33.575 2.697 34.315 ;
     RECT  21.456 34.079 21.474 34.421 ;
     RECT  23.508 33.809 32.958 34.421 ;
     RECT  23.508 34.421 28.35 34.529 ;
     RECT  29.088 34.421 32.958 34.529 ;
     RECT  29.124 34.529 32.958 34.591 ;
     RECT  2.304 34.315 2.697 34.651 ;
     RECT  3.816 33.809 4.662 34.651 ;
     RECT  2.304 34.651 4.662 34.781 ;
     RECT  23.508 34.529 28.242 34.795 ;
     RECT  2.415 34.781 4.662 34.925 ;
     RECT  22.968 34.795 28.242 35.159 ;
     RECT  3.564 34.925 4.662 35.311 ;
     RECT  5.436 34.079 9.918 35.311 ;
     RECT  23.292 35.159 28.242 35.357 ;
     RECT  3.564 35.311 9.918 35.465 ;
     RECT  2.415 34.925 2.697 35.611 ;
     RECT  29.124 34.591 33.57 35.671 ;
     RECT  2.304 35.611 2.697 35.735 ;
     RECT  29.088 35.671 33.57 35.837 ;
     RECT  3.996 35.465 9.918 35.969 ;
     RECT  34.815 33.583 35.73 36.013 ;
     RECT  34.74 36.013 35.73 36.085 ;
     RECT  42.912 27.635 42.93 36.347 ;
     RECT  29.124 35.837 33.57 36.355 ;
     RECT  34.56 36.085 35.73 36.355 ;
     RECT  29.124 36.355 35.73 36.419 ;
     RECT  2.34 35.735 2.697 36.475 ;
     RECT  2.304 36.475 2.697 36.517 ;
     RECT  3.996 35.969 4.626 36.517 ;
     RECT  2.304 36.517 4.626 36.545 ;
     RECT  2.415 36.545 4.626 36.859 ;
     RECT  5.652 35.969 9.918 36.895 ;
     RECT  2.415 36.859 4.806 36.931 ;
     RECT  5.616 36.895 9.918 36.931 ;
     RECT  2.415 36.931 9.918 37.435 ;
     RECT  29.196 36.419 35.73 37.597 ;
     RECT  29.052 37.597 35.73 37.613 ;
     RECT  2.415 37.435 10.134 37.771 ;
     RECT  23.472 35.357 28.242 37.831 ;
     RECT  29.052 37.613 33.57 37.831 ;
     RECT  12.744 33.385 14.274 37.859 ;
     RECT  2.304 37.771 10.134 37.895 ;
     RECT  12.744 37.859 14.166 37.939 ;
     RECT  12.42 37.939 14.166 37.975 ;
     RECT  2.415 37.895 10.134 38.003 ;
     RECT  23.472 37.831 33.57 38.003 ;
     RECT  11.484 37.975 11.502 38.011 ;
     RECT  12.312 37.975 14.166 38.011 ;
     RECT  11.484 38.011 14.166 38.045 ;
     RECT  0.108 38.173 0.126 38.237 ;
     RECT  2.415 38.003 6.138 38.399 ;
     RECT  2.415 38.399 3.222 38.435 ;
     RECT  4.14 38.399 6.138 38.435 ;
     RECT  2.415 38.435 2.697 38.635 ;
     RECT  34.74 37.613 35.73 38.635 ;
     RECT  34.596 38.635 35.73 38.641 ;
     RECT  4.284 38.435 6.138 38.669 ;
     RECT  11.52 38.045 14.166 38.669 ;
     RECT  2.304 38.635 2.697 38.705 ;
     RECT  11.52 38.669 11.538 38.705 ;
     RECT  23.472 38.003 28.494 38.749 ;
     RECT  29.376 38.003 33.57 38.749 ;
     RECT  12.276 38.669 14.166 38.765 ;
     RECT  23.472 38.749 33.57 38.821 ;
     RECT  4.284 38.669 5.814 38.939 ;
     RECT  5.652 38.939 5.814 38.975 ;
     RECT  23.472 38.821 33.822 39.055 ;
     RECT  34.596 38.641 35.874 39.055 ;
     RECT  6.912 38.003 10.134 39.091 ;
     RECT  13.215 38.765 14.166 39.091 ;
     RECT  23.472 39.055 35.874 39.091 ;
     RECT  13.215 39.091 14.49 39.209 ;
     RECT  23.472 39.091 36.054 39.281 ;
     RECT  6.912 39.091 10.926 39.317 ;
     RECT  6.912 39.317 10.134 39.479 ;
     RECT  4.284 38.939 4.554 39.515 ;
     RECT  5.76 38.975 5.814 39.547 ;
     RECT  23.472 39.281 35.982 39.749 ;
     RECT  4.284 39.515 4.302 39.901 ;
     RECT  13.215 39.209 14.346 39.901 ;
     RECT  2.415 38.705 2.697 39.931 ;
     RECT  7.815 39.479 10.134 40.019 ;
     RECT  12.276 38.765 12.294 40.027 ;
     RECT  13.176 39.901 14.346 40.027 ;
     RECT  2.304 39.931 2.697 40.055 ;
     RECT  2.415 40.055 2.697 40.135 ;
     RECT  4.212 39.901 4.302 40.135 ;
     RECT  5.76 39.547 5.886 40.165 ;
     RECT  6.912 39.479 7.074 40.165 ;
     RECT  2.415 40.135 3.294 40.171 ;
     RECT  4.104 40.135 4.302 40.171 ;
     RECT  5.76 40.165 7.074 40.171 ;
     RECT  12.276 40.027 14.346 40.261 ;
     RECT  19.656 38.515 19.674 40.261 ;
     RECT  2.415 40.171 4.302 40.289 ;
     RECT  12.276 40.261 14.886 40.397 ;
     RECT  13.176 40.397 14.346 40.433 ;
     RECT  2.415 40.289 3.294 40.445 ;
     RECT  23.472 39.749 35.766 40.559 ;
     RECT  2.415 40.445 2.862 40.595 ;
     RECT  4.212 40.289 4.302 40.597 ;
     RECT  5.724 40.171 7.074 40.675 ;
     RECT  7.815 40.019 8.298 40.675 ;
     RECT  4.212 40.597 4.842 40.711 ;
     RECT  5.616 40.675 8.298 40.711 ;
     RECT  2.415 40.595 2.826 40.795 ;
     RECT  2.304 40.795 2.826 40.865 ;
     RECT  4.212 40.711 8.298 40.865 ;
     RECT  6.624 40.865 8.298 40.945 ;
     RECT  6.624 40.945 8.622 41.009 ;
     RECT  6.768 41.009 8.622 41.261 ;
     RECT  7.812 41.261 8.622 41.369 ;
     RECT  6.876 41.261 6.966 41.477 ;
     RECT  2.415 40.865 2.826 41.647 ;
     RECT  6.948 41.477 6.966 41.675 ;
     RECT  2.304 41.647 2.826 41.707 ;
     RECT  9.432 40.019 10.134 41.719 ;
     RECT  11.088 41.449 11.106 41.719 ;
     RECT  4.212 40.865 5.814 41.755 ;
     RECT  2.304 41.707 3.294 41.791 ;
     RECT  4.104 41.755 5.814 41.791 ;
     RECT  9.432 41.719 11.106 41.791 ;
     RECT  7.815 41.369 8.622 41.881 ;
     RECT  9.432 41.791 11.322 41.881 ;
     RECT  12.276 40.397 12.294 41.899 ;
     RECT  13.215 40.433 14.346 41.899 ;
     RECT  2.304 41.791 5.814 41.909 ;
     RECT  2.304 41.909 3.15 41.945 ;
     RECT  7.815 41.881 11.322 41.981 ;
     RECT  9.432 41.981 11.322 42.053 ;
     RECT  12.276 41.899 14.346 42.179 ;
     RECT  9.432 42.053 11.214 42.215 ;
     RECT  4.824 41.909 5.814 42.251 ;
     RECT  5.004 42.251 5.814 42.287 ;
     RECT  5.004 42.287 5.706 42.449 ;
     RECT  7.815 41.981 8.478 42.457 ;
     RECT  3.96 41.909 3.978 42.485 ;
     RECT  6.624 42.427 6.642 42.485 ;
     RECT  7.416 42.457 8.478 42.601 ;
     RECT  6.768 42.601 8.478 42.719 ;
     RECT  5.256 42.449 5.706 42.755 ;
     RECT  7.416 42.719 8.478 42.755 ;
     RECT  2.304 41.945 2.697 43.025 ;
     RECT  7.488 42.755 8.478 43.259 ;
     RECT  23.472 40.559 35.694 43.259 ;
     RECT  5.688 42.755 5.706 43.295 ;
     RECT  23.472 43.259 35.658 43.295 ;
     RECT  7.488 43.259 8.442 43.367 ;
     RECT  7.488 43.367 8.298 43.403 ;
     RECT  15.336 40.405 15.354 43.411 ;
     RECT  11.196 42.215 11.214 43.439 ;
     RECT  7.815 43.403 8.298 43.529 ;
     RECT  15.336 43.411 15.786 43.529 ;
     RECT  12.312 42.179 12.33 43.843 ;
     RECT  9.432 42.215 10.134 44.041 ;
     RECT  12.168 43.843 12.33 44.059 ;
     RECT  13.215 42.179 14.346 44.059 ;
     RECT  31.428 43.295 35.658 44.069 ;
     RECT  23.472 43.295 30.69 44.077 ;
     RECT  31.428 44.069 35.622 44.077 ;
     RECT  9.432 44.041 10.278 44.249 ;
     RECT  12.168 44.059 14.346 44.311 ;
     RECT  19.656 40.261 20.286 44.311 ;
     RECT  9.9 44.249 10.278 44.419 ;
     RECT  11.952 44.311 14.346 44.419 ;
     RECT  11.844 44.419 14.346 44.455 ;
     RECT  9.9 44.419 10.89 44.477 ;
     RECT  11.664 44.455 14.346 44.491 ;
     RECT  9.9 44.477 10.278 44.609 ;
     RECT  23.472 44.077 35.622 44.609 ;
     RECT  17.1 43.645 17.118 44.789 ;
     RECT  18.615 3.371 18.897 44.923 ;
     RECT  17.928 44.923 18.897 44.959 ;
     RECT  19.62 44.311 20.286 44.959 ;
     RECT  11.016 44.491 14.346 45.149 ;
     RECT  11.016 45.149 11.97 45.155 ;
     RECT  11.052 45.155 11.97 45.221 ;
     RECT  12.996 45.149 14.346 45.391 ;
     RECT  15.336 43.529 15.354 45.391 ;
     RECT  11.052 45.221 11.826 45.419 ;
     RECT  12.996 45.391 15.354 45.419 ;
     RECT  36.648 45.121 36.666 45.419 ;
     RECT  11.052 45.419 11.754 45.455 ;
     RECT  17.928 44.959 20.286 45.463 ;
     RECT  13.215 45.419 15.354 45.491 ;
     RECT  11.052 45.455 11.178 45.563 ;
     RECT  23.472 44.609 35.097 45.761 ;
     RECT  11.052 45.563 11.07 45.959 ;
     RECT  23.472 45.761 31.086 45.995 ;
     RECT  17.352 45.463 20.286 46.111 ;
     RECT  31.824 45.761 35.097 46.139 ;
     RECT  23.472 45.995 30.798 46.273 ;
     RECT  14.328 45.491 15.354 46.309 ;
     RECT  17.352 46.111 20.502 46.345 ;
     RECT  32.436 46.139 35.097 46.345 ;
     RECT  13.215 45.491 13.497 46.381 ;
     RECT  14.328 46.309 16.254 46.381 ;
     RECT  9.9 44.609 9.918 46.499 ;
     RECT  13.215 46.381 16.254 46.535 ;
     RECT  22.824 46.273 30.798 46.643 ;
     RECT  17.352 46.345 21.186 46.645 ;
     RECT  17.064 46.645 21.186 46.651 ;
     RECT  10.836 46.543 10.854 46.679 ;
     RECT  13.215 46.535 15.822 46.679 ;
     RECT  17.064 46.651 21.51 46.685 ;
     RECT  22.824 46.643 27.198 46.741 ;
     RECT  27.936 46.643 30.798 46.769 ;
     RECT  17.28 46.685 21.51 46.921 ;
     RECT  28.872 46.769 30.798 47.191 ;
     RECT  37.548 45.967 37.566 47.191 ;
     RECT  36.18 47.275 36.198 47.281 ;
     RECT  37.116 47.191 37.566 47.281 ;
     RECT  36.18 47.281 38.106 47.309 ;
     RECT  38.88 46.777 38.898 47.309 ;
     RECT  28.872 47.191 31.518 47.353 ;
     RECT  32.436 46.345 35.154 47.353 ;
     RECT  13.215 46.679 15.75 47.357 ;
     RECT  28.872 47.353 35.154 47.389 ;
     RECT  36.18 47.309 36.63 47.389 ;
     RECT  17.28 46.921 21.582 47.425 ;
     RECT  22.644 46.741 27.198 47.425 ;
     RECT  14.256 47.357 15.75 47.453 ;
     RECT  16.668 47.425 21.582 47.461 ;
     RECT  37.44 47.309 38.106 47.461 ;
     RECT  14.256 47.453 14.994 47.579 ;
     RECT  28.872 47.389 36.63 47.587 ;
     RECT  15.732 47.453 15.75 47.659 ;
     RECT  16.668 47.461 21.654 47.659 ;
     RECT  22.608 47.425 27.198 47.695 ;
     RECT  22.392 47.695 27.198 47.731 ;
     RECT  27.936 46.769 27.954 47.731 ;
     RECT  28.836 47.587 36.63 47.731 ;
     RECT  14.436 47.579 14.994 47.759 ;
     RECT  14.544 47.759 14.994 47.849 ;
     RECT  37.44 47.461 38.43 47.849 ;
     RECT  22.392 47.731 27.954 47.851 ;
     RECT  28.692 47.731 36.63 47.851 ;
     RECT  15.732 47.659 21.654 48.001 ;
     RECT  22.392 47.851 36.63 48.001 ;
     RECT  14.616 47.849 14.994 48.119 ;
     RECT  15.732 48.001 36.63 48.163 ;
     RECT  37.44 47.849 38.106 48.163 ;
     RECT  14.688 48.119 14.994 48.541 ;
     RECT  15.732 48.163 38.106 48.541 ;
     RECT  14.688 48.541 38.106 48.775 ;
     RECT  14.688 48.775 38.178 49.045 ;
     RECT  14.544 49.045 38.178 49.315 ;
     RECT  14.508 49.315 38.178 49.351 ;
     RECT  2.415 43.025 2.697 49.427 ;
     RECT  7.815 43.529 8.097 49.427 ;
     RECT  13.215 47.357 13.497 49.427 ;
     RECT  40.215 33.179 40.497 49.427 ;
     RECT  45.615 33.035 45.897 49.427 ;
     RECT  14.4 49.351 38.178 49.469 ;
     RECT  14.4 49.469 37.638 49.505 ;
     RECT  14.652 49.505 37.638 49.517 ;
     RECT  15.624 49.517 17.874 49.565 ;
     RECT  26.856 49.517 32.994 49.565 ;
     RECT  34.2 49.517 37.638 49.565 ;
     RECT  15.624 49.565 17.478 49.577 ;
     RECT  18.615 49.517 19.422 49.577 ;
     RECT  20.376 49.517 25.65 49.577 ;
     RECT  26.856 49.565 29.682 49.577 ;
     RECT  30.852 49.565 30.87 49.577 ;
     RECT  31.608 49.565 32.598 49.577 ;
     RECT  34.2 49.565 37.35 49.577 ;
     RECT  2.415 49.427 2.505 49.697 ;
     RECT  7.815 49.427 7.905 49.697 ;
     RECT  13.215 49.427 13.305 49.697 ;
     RECT  18.615 49.577 18.705 49.697 ;
     RECT  23.832 49.577 24.105 49.697 ;
     RECT  34.74 49.577 34.905 49.697 ;
     RECT  40.215 49.427 40.305 49.697 ;
     RECT  45.615 49.427 45.705 49.697 ;
     RECT  28.98 49.577 29.574 49.805 ;
     RECT  34.74 49.697 34.758 49.853 ;
     RECT  27.288 49.577 27.306 50.189 ;
     RECT  14.652 49.517 14.67 50.765 ;
     RECT  16.488 49.577 16.506 50.765 ;
     RECT  22.104 49.577 22.122 50.765 ;
     RECT  23.832 49.697 23.85 50.765 ;
     RECT  25.632 49.577 25.65 50.765 ;
     RECT  28.98 49.805 28.998 50.765 ;
     RECT  31.896 49.577 31.914 50.765 ;
     RECT  36.36 49.577 36.378 50.765 ;
    LAYER M4 ;
     RECT  0.06 8.832 2.408 42.984 ;
     RECT  2.408 2.148 2.512 49.692 ;
     RECT  2.512 2.418 2.704 49.422 ;
     RECT  2.704 15.312 2.801 16.632 ;
     RECT  2.704 25.248 2.801 26.664 ;
     RECT  2.704 9.072 2.837 11.448 ;
     RECT  2.704 12.768 2.837 13.608 ;
     RECT  2.704 20.064 2.837 20.088 ;
     RECT  2.704 27.888 2.837 29.112 ;
     RECT  2.704 30.864 2.837 30.888 ;
     RECT  2.704 36.864 2.837 36.936 ;
     RECT  2.704 40.368 2.837 41.736 ;
     RECT  2.837 40.368 2.873 40.632 ;
     RECT  2.837 9.072 2.981 10.584 ;
     RECT  2.801 15.312 2.981 15.864 ;
     RECT  2.981 9.072 3.305 9.384 ;
     RECT  2.704 17.616 3.305 18.84 ;
     RECT  2.704 31.872 3.305 31.896 ;
     RECT  2.873 40.416 3.305 40.632 ;
     RECT  2.981 10.56 3.34 10.584 ;
     RECT  3.305 17.616 3.34 18.024 ;
     RECT  2.837 41.712 3.34 41.736 ;
     RECT  2.704 34.656 3.341 34.68 ;
     RECT  2.837 27.888 3.347 27.912 ;
     RECT  2.837 29.088 3.377 29.112 ;
     RECT  2.704 22.848 3.733 22.872 ;
     RECT  2.801 25.68 4.741 26.664 ;
     RECT  4.705 27.936 4.741 27.96 ;
     RECT  3.877 24.528 4.785 24.552 ;
     RECT  4.741 25.68 4.785 27.96 ;
     RECT  2.981 15.84 4.796 15.864 ;
     RECT  3.733 22.272 4.796 22.872 ;
     RECT  4.789 11.232 4.813 11.256 ;
     RECT  2.837 12.768 4.813 12.792 ;
     RECT  2.704 33.072 4.813 33.096 ;
     RECT  4.785 24.528 4.817 27.96 ;
     RECT  3.305 9.36 4.837 9.384 ;
     RECT  4.813 10.848 4.837 11.256 ;
     RECT  4.813 33.072 4.837 33.672 ;
     RECT  2.704 38.112 4.844 38.136 ;
     RECT  2.704 21.216 4.849 21.24 ;
     RECT  4.796 22.272 4.849 23.352 ;
     RECT  4.837 32.112 4.849 33.672 ;
     RECT  4.813 12.768 4.853 13.128 ;
     RECT  4.837 9.36 4.876 11.256 ;
     RECT  4.796 15.84 4.883 16.296 ;
     RECT  2.837 36.864 4.883 36.888 ;
     RECT  4.844 38.112 4.885 38.664 ;
     RECT  4.849 21.216 4.889 23.352 ;
     RECT  4.876 9.36 4.897 10.872 ;
     RECT  4.897 9.36 4.917 10.104 ;
     RECT  4.849 31.92 4.924 33.672 ;
     RECT  4.813 30.144 4.931 30.168 ;
     RECT  4.885 37.632 4.931 38.664 ;
     RECT  4.924 31.92 4.933 31.944 ;
     RECT  4.817 24.528 5.069 25.704 ;
     RECT  4.889 21.312 5.123 23.352 ;
     RECT  3.34 18 5.173 18.024 ;
     RECT  5.173 17.088 5.219 18.024 ;
     RECT  5.219 17.088 5.26 17.112 ;
     RECT  4.849 19.824 5.459 19.848 ;
     RECT  5.381 18.768 5.465 18.792 ;
     RECT  4.853 13.104 5.533 13.128 ;
     RECT  5.123 21.312 5.603 22.296 ;
     RECT  5.533 13.104 5.617 13.656 ;
     RECT  4.924 33.024 5.789 33.672 ;
     RECT  5.603 22.176 6.005 22.296 ;
     RECT  4.917 10.08 6.109 10.104 ;
     RECT  5.069 24.528 6.217 25.08 ;
     RECT  6.217 24.192 6.277 25.08 ;
     RECT  6.245 34.176 6.277 34.2 ;
     RECT  4.837 35.328 6.277 35.352 ;
     RECT  4.785 14.784 6.329 14.808 ;
     RECT  6.277 23.664 6.365 25.704 ;
     RECT  6.109 9.408 6.421 10.104 ;
     RECT  5.857 39.552 6.428 39.576 ;
     RECT  3.305 40.608 6.428 40.632 ;
     RECT  6.277 34.176 6.433 35.352 ;
     RECT  5.557 19.248 6.469 19.272 ;
     RECT  4.817 27.216 6.469 27.96 ;
     RECT  5.789 33.024 6.469 33.048 ;
     RECT  6.389 11.424 6.473 11.448 ;
     RECT  5.617 13.104 6.473 13.128 ;
     RECT  6.365 23.664 6.473 25.176 ;
     RECT  6.433 34.176 6.473 35.976 ;
     RECT  6.428 39.552 6.473 40.632 ;
     RECT  6.473 39.552 6.515 40.2 ;
     RECT  6.572 42.432 6.613 42.456 ;
     RECT  6.469 19.248 6.649 20.232 ;
     RECT  6.613 42.432 6.659 43.368 ;
     RECT  5.785 30.672 6.716 30.696 ;
     RECT  6.469 27.216 6.793 28.824 ;
     RECT  6.469 32.16 6.803 33.048 ;
     RECT  6.803 32.496 7.009 33.048 ;
     RECT  6.793 27.216 7.297 29.112 ;
     RECT  6.716 30.672 7.297 30.888 ;
     RECT  6.005 22.176 7.405 22.2 ;
     RECT  6.433 15.36 7.429 15.384 ;
     RECT  6.473 24.096 7.441 25.176 ;
     RECT  7.441 24.096 7.477 26.088 ;
     RECT  7.297 27.216 7.525 30.888 ;
     RECT  7.436 12.24 7.649 12.264 ;
     RECT  7.525 27.216 7.765 31.368 ;
     RECT  7.009 32.496 7.765 33.144 ;
     RECT  6.421 9.408 7.808 10.392 ;
     RECT  7.649 11.376 7.808 12.264 ;
     RECT  7.436 13.872 7.808 13.896 ;
     RECT  7.429 15.36 7.808 15.864 ;
     RECT  6.829 17.088 7.808 17.112 ;
     RECT  6.649 19.248 7.808 21.144 ;
     RECT  7.405 22.176 7.808 22.584 ;
     RECT  7.477 24 7.808 26.088 ;
     RECT  7.765 27.216 7.808 33.144 ;
     RECT  6.473 34.176 7.808 34.392 ;
     RECT  6.473 35.952 7.808 35.976 ;
     RECT  4.931 37.632 7.808 37.656 ;
     RECT  6.515 39.552 7.808 39.576 ;
     RECT  6.613 41.232 7.808 41.256 ;
     RECT  6.659 43.344 7.808 43.368 ;
     RECT  6.469 44.592 7.808 44.616 ;
     RECT  7.808 2.148 7.912 49.692 ;
     RECT  7.912 2.418 8.104 49.422 ;
     RECT  8.104 27.168 8.129 32.184 ;
     RECT  8.104 37.632 8.165 39.576 ;
     RECT  8.104 22.464 8.237 24.216 ;
     RECT  8.237 22.464 8.243 22.488 ;
     RECT  8.237 23.952 8.243 24.216 ;
     RECT  8.129 27.168 8.243 29.688 ;
     RECT  8.165 37.632 8.243 38.808 ;
     RECT  8.104 25.68 8.245 25.704 ;
     RECT  8.243 24.192 8.273 24.216 ;
     RECT  8.243 28.128 8.531 29.688 ;
     RECT  8.104 20.64 8.597 20.664 ;
     RECT  8.531 29.664 8.633 29.688 ;
     RECT  8.129 30.672 8.675 32.184 ;
     RECT  8.104 44.592 10.861 44.616 ;
     RECT  10.861 44.448 10.988 44.616 ;
     RECT  10.988 44.448 11.075 45.144 ;
     RECT  8.243 38.016 11.513 38.04 ;
     RECT  11.075 44.448 12.812 44.616 ;
     RECT  12.812 44.448 12.86 45 ;
     RECT  8.104 19.248 13.208 19.272 ;
     RECT  12.877 38.736 13.208 38.76 ;
     RECT  12.589 40.032 13.208 40.056 ;
     RECT  9.817 41.904 13.208 41.928 ;
     RECT  12.86 44.064 13.208 45 ;
     RECT  13.208 2.148 13.312 49.692 ;
     RECT  13.312 2.418 13.504 49.422 ;
     RECT  13.504 46.752 13.961 47.352 ;
     RECT  13.504 44.592 14.033 45 ;
     RECT  13.504 49.344 14.537 49.368 ;
     RECT  14.641 50.736 14.915 50.76 ;
     RECT  13.961 47.328 15.005 47.352 ;
     RECT  15.301 49.488 15.401 49.512 ;
     RECT  16.477 50.736 16.643 50.76 ;
     RECT  16.261 47.904 16.733 47.928 ;
     RECT  17.053 46.656 17.125 46.68 ;
     RECT  17.125 46.656 17.171 47.352 ;
     RECT  17.171 47.328 17.309 47.352 ;
     RECT  17.233 48.432 18.025 48.456 ;
     RECT  18.025 47.904 18.133 48.456 ;
     RECT  15.613 49.536 18.133 49.56 ;
     RECT  18.133 47.904 18.565 49.56 ;
     RECT  13.504 19.248 18.608 19.272 ;
     RECT  13.504 25.776 18.608 25.8 ;
     RECT  14.033 44.592 18.608 44.616 ;
     RECT  18.565 47.04 18.608 49.56 ;
     RECT  18.608 2.148 18.712 49.692 ;
     RECT  18.712 2.148 18.904 49.56 ;
     RECT  18.904 44.592 19.379 45 ;
     RECT  18.904 2.832 19.763 3.336 ;
     RECT  18.904 49.536 20.053 49.56 ;
     RECT  20.053 49.488 20.153 49.56 ;
     RECT  18.904 19.248 20.365 19.272 ;
     RECT  20.365 19.104 20.405 19.272 ;
     RECT  19.763 3.312 20.588 3.336 ;
     RECT  18.904 46.608 20.657 48.264 ;
     RECT  20.588 3.312 20.675 4.104 ;
     RECT  20.657 46.704 20.765 48.264 ;
     RECT  20.405 19.104 21.049 19.128 ;
     RECT  20.675 3.312 21.053 3.336 ;
     RECT  20.765 46.752 21.125 48.264 ;
     RECT  22.093 50.736 22.259 50.76 ;
     RECT  22.193 0.576 22.277 0.6 ;
     RECT  21.125 46.752 22.741 47.304 ;
     RECT  18.904 25.776 22.981 25.8 ;
     RECT  22.981 25.776 23.029 26.088 ;
     RECT  22.957 34.8 23.029 34.824 ;
     RECT  21.877 3.456 23.605 3.48 ;
     RECT  21.661 4.896 23.605 4.92 ;
     RECT  23.029 34.8 23.605 35.736 ;
     RECT  22.741 46.752 23.641 47.928 ;
     RECT  23.605 34.704 23.708 35.736 ;
     RECT  23.821 50.736 23.987 50.76 ;
     RECT  18.961 1.728 24.008 1.752 ;
     RECT  23.605 3.456 24.008 4.92 ;
     RECT  21.049 18.96 24.008 19.128 ;
     RECT  23.029 25.68 24.008 26.088 ;
     RECT  23.708 34.704 24.008 36.12 ;
     RECT  19.379 44.592 24.008 44.616 ;
     RECT  23.641 46.176 24.008 47.928 ;
     RECT  20.153 49.536 24.008 49.56 ;
     RECT  23.929 0.576 24.013 0.6 ;
     RECT  24.008 1.728 24.112 49.692 ;
     RECT  24.112 1.728 24.304 49.56 ;
     RECT  24.304 25.776 24.401 26.088 ;
     RECT  24.304 46.752 24.419 47.4 ;
     RECT  24.401 26.064 24.725 26.088 ;
     RECT  24.304 49.536 25.283 49.56 ;
     RECT  24.304 42.192 25.309 43.608 ;
     RECT  24.304 37.872 25.344 38.232 ;
     RECT  25.397 38.784 25.436 38.808 ;
     RECT  25.436 38.784 25.481 39.048 ;
     RECT  25.481 39.024 25.523 39.048 ;
     RECT  25.309 42.624 25.523 43.608 ;
     RECT  25.523 42.624 25.625 42.648 ;
     RECT  25.429 3.216 25.697 3.24 ;
     RECT  25.621 50.736 25.715 50.76 ;
     RECT  24.304 4.896 25.801 4.92 ;
     RECT  24.304 34.704 25.945 36.168 ;
     RECT  25.285 44.64 26.017 44.664 ;
     RECT  26.017 43.776 26.237 44.664 ;
     RECT  25.801 3.936 26.273 4.92 ;
     RECT  24.419 46.752 26.557 47.304 ;
     RECT  26.233 45.696 26.629 45.72 ;
     RECT  26.557 46.752 26.629 47.88 ;
     RECT  26.101 49.488 26.633 49.512 ;
     RECT  25.657 33.648 26.817 33.672 ;
     RECT  25.945 34.704 26.817 36.6 ;
     RECT  26.737 43.632 26.849 43.656 ;
     RECT  25.369 37.584 26.869 37.608 ;
     RECT  26.869 37.584 27.013 37.656 ;
     RECT  26.981 42.768 27.065 42.84 ;
     RECT  27.013 37.584 27.1 38.184 ;
     RECT  26.845 49.536 27.277 49.56 ;
     RECT  26.629 45.696 27.317 47.88 ;
     RECT  27.277 49.536 27.443 50.184 ;
     RECT  26.817 33.648 27.497 36.6 ;
     RECT  27.169 3.84 27.5 3.864 ;
     RECT  26.273 4.896 27.5 4.92 ;
     RECT  27.5 3.84 27.541 4.92 ;
     RECT  27.497 33.648 27.605 36.36 ;
     RECT  27.317 46.368 27.749 47.88 ;
     RECT  27.74 39.312 27.817 39.336 ;
     RECT  27.605 35.232 27.821 36.36 ;
     RECT  27.817 38.784 27.827 39.336 ;
     RECT  27.827 38.784 27.901 38.808 ;
     RECT  26.237 44.64 27.965 44.664 ;
     RECT  27.605 33.648 28.001 34.2 ;
     RECT  27.541 3.408 28.141 4.92 ;
     RECT  28.141 3.36 28.225 4.92 ;
     RECT  27.1 37.584 28.316 37.608 ;
     RECT  28.316 37.584 28.403 37.992 ;
     RECT  27.065 42.816 28.429 42.84 ;
     RECT  24.304 18.96 28.501 18.984 ;
     RECT  28.429 42.816 28.609 42.984 ;
     RECT  28.001 33.648 29.077 34.056 ;
     RECT  27.821 35.328 29.077 36.36 ;
     RECT  29.005 40.56 29.077 40.584 ;
     RECT  28.969 50.736 29.171 50.76 ;
     RECT  27.749 46.752 29.221 47.88 ;
     RECT  29.041 32.256 29.257 32.28 ;
     RECT  29.077 33.648 29.269 36.36 ;
     RECT  24.304 1.728 29.408 1.752 ;
     RECT  28.225 3.408 29.408 4.92 ;
     RECT  28.501 18.96 29.408 19.368 ;
     RECT  28.741 26.64 29.408 26.664 ;
     RECT  29.257 32.016 29.408 32.28 ;
     RECT  29.269 33.648 29.408 37.128 ;
     RECT  29.077 40.56 29.408 40.632 ;
     RECT  27.743 41.616 29.408 41.64 ;
     RECT  28.609 42.816 29.408 43.32 ;
     RECT  29.221 46.704 29.408 47.88 ;
     RECT  27.443 49.536 29.408 49.56 ;
     RECT  29.408 1.728 29.545 49.692 ;
     RECT  29.545 1.728 29.629 49.8 ;
     RECT  29.629 1.728 29.704 49.56 ;
     RECT  29.704 42.24 29.945 44.136 ;
     RECT  29.945 43.296 30.089 44.136 ;
     RECT  29.704 45.792 30.179 48.072 ;
     RECT  30.179 45.792 30.275 47.832 ;
     RECT  29.704 38.976 30.557 39 ;
     RECT  29.704 40.608 30.665 40.632 ;
     RECT  29.704 34.656 30.755 37.416 ;
     RECT  29.704 33.648 30.757 33.672 ;
     RECT  30.755 35.136 30.773 37.416 ;
     RECT  30.773 35.136 30.796 37.368 ;
     RECT  30.757 33.648 30.803 33.96 ;
     RECT  29.704 3.456 30.881 3.96 ;
     RECT  29.704 31.392 30.917 32.328 ;
     RECT  30.917 31.392 31.025 32.184 ;
     RECT  29.945 42.24 31.057 42.264 ;
     RECT  30.913 40.416 31.385 40.44 ;
     RECT  31.34 2.832 31.427 2.856 ;
     RECT  31.273 38.784 31.487 38.808 ;
     RECT  31.057 42.24 31.525 42.792 ;
     RECT  30.089 44.112 31.525 44.136 ;
     RECT  30.881 3.888 31.601 3.96 ;
     RECT  31.487 38.64 31.633 38.808 ;
     RECT  30.803 33.936 31.637 33.96 ;
     RECT  31.633 38.64 31.667 39.048 ;
     RECT  31.667 38.736 31.669 39.048 ;
     RECT  31.525 42.24 31.745 44.136 ;
     RECT  31.745 44.112 31.885 44.136 ;
     RECT  31.669 38.736 32.051 39.288 ;
     RECT  31.601 3.888 32.141 3.912 ;
     RECT  31.885 50.736 32.195 50.76 ;
     RECT  32.051 38.784 32.393 39.288 ;
     RECT  31.745 42.24 32.429 42.984 ;
     RECT  30.796 35.232 32.461 37.368 ;
     RECT  31.885 44.112 32.573 45 ;
     RECT  32.461 35.136 32.605 37.368 ;
     RECT  31.025 31.392 32.641 31.416 ;
     RECT  29.704 1.728 32.653 1.752 ;
     RECT  30.275 46.752 32.713 47.832 ;
     RECT  32.605 35.136 32.717 37.608 ;
     RECT  32.636 2.736 32.723 2.76 ;
     RECT  32.641 30.816 32.725 31.416 ;
     RECT  32.717 35.28 32.908 37.608 ;
     RECT  32.821 40.272 32.929 40.296 ;
     RECT  29.704 49.536 33.059 49.56 ;
     RECT  32.929 40.128 33.077 40.296 ;
     RECT  32.429 42.24 33.077 42.792 ;
     RECT  33.077 40.272 33.113 40.296 ;
     RECT  32.393 38.784 33.212 39.048 ;
     RECT  32.908 35.28 33.299 36.408 ;
     RECT  33.217 41.616 33.301 41.64 ;
     RECT  33.077 42.768 33.437 42.792 ;
     RECT  33.5 3.936 33.587 3.96 ;
     RECT  32.725 31.344 33.587 31.416 ;
     RECT  33.587 31.392 33.653 31.416 ;
     RECT  32.713 46.752 33.697 47.88 ;
     RECT  32.573 44.112 33.721 44.136 ;
     RECT  33.637 45.168 33.721 45.192 ;
     RECT  33.212 38.736 33.757 39.048 ;
     RECT  33.721 44.112 33.761 45.192 ;
     RECT  33.757 38.736 34.165 39.24 ;
     RECT  33.445 49.488 34.189 49.512 ;
     RECT  34.165 38.64 34.501 39.24 ;
     RECT  34.46 40.704 34.501 40.728 ;
     RECT  33.761 44.64 34.501 45.192 ;
     RECT  34.189 49.488 34.7 49.56 ;
     RECT  34.7 49.488 34.787 49.848 ;
     RECT  29.704 26.64 34.808 26.664 ;
     RECT  31.957 32.736 34.808 32.76 ;
     RECT  33.299 36.384 34.808 36.408 ;
     RECT  32.908 37.584 34.808 37.608 ;
     RECT  34.501 38.64 34.808 40.728 ;
     RECT  34.501 44.64 34.808 45.288 ;
     RECT  33.697 46.896 34.808 47.88 ;
     RECT  34.787 49.488 34.808 49.692 ;
     RECT  34.808 2.148 34.912 49.692 ;
     RECT  34.912 2.418 35.104 49.56 ;
     RECT  35.104 47.808 36.14 47.832 ;
     RECT  36.14 47.28 36.227 47.832 ;
     RECT  36.349 50.736 36.515 50.76 ;
     RECT  35.104 45.168 36.677 45.288 ;
     RECT  36.227 47.808 37.469 47.832 ;
     RECT  35.104 49.536 37.811 49.56 ;
     RECT  35.104 26.64 40.208 26.664 ;
     RECT  35.104 32.736 40.208 32.76 ;
     RECT  40.208 2.148 40.312 49.692 ;
     RECT  40.312 2.418 40.504 49.422 ;
     RECT  40.504 26.64 42.312 26.664 ;
     RECT  42.312 26.64 42.361 27.336 ;
     RECT  40.504 32.736 42.419 32.76 ;
     RECT  42.361 26.208 42.445 27.336 ;
     RECT  42.445 26.64 43.301 27.336 ;
     RECT  43.301 26.64 43.625 26.664 ;
     RECT  43.945 25.056 45.565 25.08 ;
     RECT  45.565 24.48 45.608 25.08 ;
     RECT  45.529 26.256 45.608 26.28 ;
     RECT  45.608 2.148 45.712 49.692 ;
     RECT  45.712 2.418 45.904 49.422 ;
     RECT  45.904 26.256 46.828 26.808 ;
     RECT  46.828 26.256 47.125 26.28 ;
     RECT  45.904 24.48 47.171 24.504 ;
     RECT  47.125 26.016 47.171 26.28 ;
     RECT  47.171 26.016 47.212 26.04 ;
     RECT  50.173 25.44 50.677 25.464 ;
     RECT  50.641 27.168 50.677 27.192 ;
     RECT  50.677 24.144 50.713 24.168 ;
     RECT  50.677 25.44 50.713 27.624 ;
     RECT  50.713 24.144 51.804 27.624 ;
    LAYER M5 ;
     RECT  19.2 0.016 32.616 1.763 ;
     RECT  2.4 2.137 2.52 2.151 ;
     RECT  7.8 2.137 7.92 2.151 ;
     RECT  13.2 2.137 13.32 2.151 ;
     RECT  34.8 2.137 34.92 2.151 ;
     RECT  40.2 2.137 40.32 2.151 ;
     RECT  45.6 2.137 45.72 2.151 ;
     RECT  18.6 2.137 18.912 2.821 ;
     RECT  18.6 2.821 19.752 3.301 ;
     RECT  18.6 3.301 20.664 3.347 ;
     RECT  28.176 3.349 28.2 3.397 ;
     RECT  27.552 3.397 28.2 3.877 ;
     RECT  29.4 1.763 29.712 3.877 ;
     RECT  31.392 2.821 31.416 3.923 ;
     RECT  32.688 2.725 32.712 3.925 ;
     RECT  20.64 3.347 20.664 4.115 ;
     RECT  27.552 3.877 29.712 4.115 ;
     RECT  2.4 2.151 2.712 9.061 ;
     RECT  7.8 2.151 8.112 9.397 ;
     RECT  2.4 9.061 3.288 10.595 ;
     RECT  4.848 9.349 4.872 10.883 ;
     RECT  6.432 10.069 6.456 11.459 ;
     RECT  7.632 9.397 8.112 12.229 ;
     RECT  4.8 11.221 4.824 12.803 ;
     RECT  5.568 13.621 5.592 14.773 ;
     RECT  7.488 12.229 8.112 15.829 ;
     RECT  4.848 14.773 5.592 16.307 ;
     RECT  7.44 15.829 8.112 17.123 ;
     RECT  2.4 10.595 2.712 17.605 ;
     RECT  5.184 16.307 5.592 18.035 ;
     RECT  2.4 17.605 3.288 18.851 ;
     RECT  24 1.763 24.312 19.093 ;
     RECT  7.632 17.123 8.112 19.333 ;
     RECT  5.424 18.035 5.592 19.859 ;
     RECT  6.816 19.333 8.112 21.155 ;
     RECT  5.568 19.859 5.592 21.301 ;
     RECT  5.376 21.301 5.592 21.347 ;
     RECT  5.376 21.347 5.4 21.637 ;
     RECT  7.632 21.155 8.112 22.453 ;
     RECT  7.632 22.453 8.232 22.549 ;
     RECT  5.088 21.637 5.4 23.317 ;
     RECT  4.848 23.317 5.4 23.653 ;
     RECT  7.584 22.549 8.232 23.989 ;
     RECT  7.488 23.989 8.232 24.851 ;
     RECT  4.848 23.653 6.312 25.091 ;
     RECT  5.376 25.091 6.312 25.715 ;
     RECT  13.2 2.151 13.512 25.765 ;
     RECT  23.04 19.093 24.312 26.053 ;
     RECT  22.992 26.053 24.312 26.099 ;
     RECT  45.6 2.151 45.912 26.245 ;
     RECT  47.136 24.469 47.16 26.245 ;
     RECT  45.6 26.245 47.16 26.291 ;
     RECT  5.376 25.715 5.4 26.629 ;
     RECT  28.176 4.115 29.712 26.675 ;
     RECT  45.6 26.291 46.776 26.819 ;
     RECT  4.752 26.629 5.4 27.251 ;
     RECT  2.4 18.851 2.712 27.877 ;
     RECT  5.088 27.251 5.4 27.971 ;
     RECT  7.536 24.851 8.232 28.117 ;
     RECT  2.4 27.877 3.336 29.123 ;
     RECT  7.536 28.117 8.52 29.699 ;
     RECT  7.536 29.699 8.112 30.661 ;
     RECT  32.688 3.925 33.576 30.851 ;
     RECT  6.768 30.661 8.664 31.379 ;
     RECT  33.072 30.851 33.576 31.379 ;
     RECT  2.4 29.123 2.712 31.861 ;
     RECT  4.896 30.133 4.92 31.955 ;
     RECT  7.8 31.379 8.664 32.195 ;
     RECT  6.768 31.379 6.792 32.531 ;
     RECT  42.384 26.197 42.408 32.771 ;
     RECT  4.848 32.101 4.872 33.107 ;
     RECT  29.4 26.675 29.712 34.021 ;
     RECT  28.176 26.675 28.2 34.067 ;
     RECT  6.48 33.013 6.504 34.165 ;
     RECT  2.4 31.861 3.288 34.691 ;
     RECT  26.88 34.165 26.904 34.693 ;
     RECT  30.768 33.637 30.792 34.693 ;
     RECT  22.992 26.099 23.016 34.835 ;
     RECT  30.72 34.693 30.792 35.171 ;
     RECT  26.88 34.693 27.288 35.221 ;
     RECT  30.768 35.171 30.792 35.221 ;
     RECT  33.072 31.379 33.096 35.269 ;
     RECT  33.072 35.269 33.288 35.315 ;
     RECT  24 26.099 24.312 35.317 ;
     RECT  6.288 34.165 6.504 35.363 ;
     RECT  25.44 3.205 25.464 35.797 ;
     RECT  26.88 35.221 27.48 35.797 ;
     RECT  30.768 35.221 31.656 35.987 ;
     RECT  23.04 35.317 24.312 36.133 ;
     RECT  25.44 35.797 25.512 36.179 ;
     RECT  26.88 35.797 27.864 36.325 ;
     RECT  29.28 34.021 29.712 36.325 ;
     RECT  4.848 35.317 4.872 36.899 ;
     RECT  33.264 35.315 33.288 37.093 ;
     RECT  26.88 36.325 29.712 37.139 ;
     RECT  32.832 37.093 33.288 37.573 ;
     RECT  34.8 2.151 35.112 37.573 ;
     RECT  7.8 32.195 8.112 37.621 ;
     RECT  26.88 37.139 28.392 37.667 ;
     RECT  23.04 36.133 24.408 37.861 ;
     RECT  25.44 36.179 25.464 37.861 ;
     RECT  27.024 37.667 28.392 38.003 ;
     RECT  31.632 35.987 31.656 38.629 ;
     RECT  4.896 37.621 4.92 38.675 ;
     RECT  32.832 37.573 35.112 38.675 ;
     RECT  13.2 25.765 14.04 38.725 ;
     RECT  31.536 38.629 31.656 38.725 ;
     RECT  32.832 38.675 33.288 38.725 ;
     RECT  7.8 37.621 8.232 38.819 ;
     RECT  27.024 38.003 27.864 38.819 ;
     RECT  23.04 37.861 25.464 39.013 ;
     RECT  31.536 38.725 33.288 39.203 ;
     RECT  34.8 38.675 35.112 39.781 ;
     RECT  32.832 39.203 33.288 40.307 ;
     RECT  2.4 34.691 2.712 40.405 ;
     RECT  6.48 35.363 6.504 41.221 ;
     RECT  27.024 38.819 27.816 41.651 ;
     RECT  33.264 40.307 33.288 41.651 ;
     RECT  2.4 40.405 3.288 41.747 ;
     RECT  23.04 39.013 25.512 42.227 ;
     RECT  29.4 37.139 29.712 42.229 ;
     RECT  27.024 41.651 27.048 42.803 ;
     RECT  29.4 42.229 29.832 42.851 ;
     RECT  6.48 41.221 6.648 43.379 ;
     RECT  31.536 39.203 31.56 43.379 ;
     RECT  23.04 42.227 24.408 43.573 ;
     RECT  25.488 42.227 25.512 43.573 ;
     RECT  23.04 43.573 25.512 43.619 ;
     RECT  12.912 38.725 14.04 44.437 ;
     RECT  6.48 43.379 6.504 44.627 ;
     RECT  23.04 43.619 25.32 44.627 ;
     RECT  34.512 39.781 35.112 44.629 ;
     RECT  23.76 44.627 25.32 44.675 ;
     RECT  18.6 3.347 18.912 44.965 ;
     RECT  12.864 44.437 14.04 45.011 ;
     RECT  11.04 44.437 11.064 45.155 ;
     RECT  33.888 44.629 35.112 45.157 ;
     RECT  29.4 42.851 29.712 45.781 ;
     RECT  23.76 44.675 24.408 46.211 ;
     RECT  18.6 44.965 19.368 46.643 ;
     RECT  33.648 45.157 35.112 46.931 ;
     RECT  33.648 46.931 33.672 47.029 ;
     RECT  21.072 44.581 21.096 47.269 ;
     RECT  33.408 47.029 33.672 47.315 ;
     RECT  17.136 46.645 17.16 47.363 ;
     RECT  29.4 45.781 30.264 47.363 ;
     RECT  24 46.211 24.408 47.411 ;
     RECT  20.544 47.269 21.096 47.843 ;
     RECT  26.784 46.213 26.808 47.843 ;
     RECT  36.192 45.253 36.216 47.843 ;
     RECT  33.408 47.315 33.432 47.891 ;
     RECT  29.4 47.363 30.168 48.083 ;
     RECT  20.544 47.843 20.568 48.275 ;
     RECT  13.2 45.011 14.04 49.333 ;
     RECT  13.2 49.333 14.472 49.477 ;
     RECT  18.6 46.643 18.912 49.477 ;
     RECT  34.8 46.931 35.112 49.477 ;
     RECT  13.2 49.477 15.336 49.525 ;
     RECT  18.336 49.477 18.912 49.525 ;
     RECT  20.064 49.477 20.088 49.525 ;
     RECT  24 47.411 24.312 49.525 ;
     RECT  26.112 49.477 26.568 49.525 ;
     RECT  29.4 48.083 29.712 49.525 ;
     RECT  33.456 49.477 35.112 49.525 ;
     RECT  2.4 41.747 2.712 49.689 ;
     RECT  7.8 38.819 8.112 49.689 ;
     RECT  40.2 2.151 40.512 49.689 ;
     RECT  45.6 26.819 45.912 49.689 ;
     RECT  2.4 49.689 2.52 49.703 ;
     RECT  7.8 49.689 7.92 49.703 ;
     RECT  13.2 49.525 37.8 49.703 ;
     RECT  40.2 49.689 40.32 49.703 ;
     RECT  45.6 49.689 45.72 49.703 ;
     RECT  14.016 49.703 18.36 51.792 ;
     RECT  19.632 49.703 37.8 51.792 ;
     RECT  19.2 1.763 19.752 2.137 ;
     RECT  24.312 1.763 25.464 3.205 ;
     RECT  31.392 1.763 32.616 2.725 ;
     RECT  18.912 2.137 19.752 2.821 ;
     RECT  31.392 2.725 32.688 2.821 ;
     RECT  31.416 2.821 32.688 3.923 ;
     RECT  24.312 3.205 25.44 36.133 ;
     RECT  28.2 3.349 29.4 3.877 ;
     RECT  33.576 3.925 34.8 31.379 ;
     RECT  6.456 10.069 7.632 11.459 ;
     RECT  7.488 11.459 7.632 12.229 ;
     RECT  5.592 19.333 6.816 21.155 ;
     RECT  5.424 19.859 5.568 21.301 ;
     RECT  7.584 21.155 7.632 22.549 ;
     RECT  6.312 23.653 7.584 23.989 ;
     RECT  6.312 23.989 7.488 24.851 ;
     RECT  45.912 24.469 47.136 26.245 ;
     RECT  6.312 24.851 7.536 25.715 ;
     RECT  23.016 26.099 24 34.835 ;
     RECT  28.2 26.675 29.4 34.021 ;
     RECT  8.112 29.699 8.52 30.661 ;
     RECT  6.792 31.379 7.8 32.531 ;
     RECT  6.768 32.531 7.8 33.013 ;
     RECT  6.504 33.013 7.8 41.221 ;
     RECT  29.712 33.637 30.768 34.693 ;
     RECT  28.2 34.021 29.28 34.067 ;
     RECT  25.464 34.165 26.88 35.797 ;
     RECT  29.712 34.693 30.72 35.171 ;
     RECT  23.04 34.835 24 35.317 ;
     RECT  29.712 35.171 30.768 35.987 ;
     RECT  31.656 35.221 33.072 35.315 ;
     RECT  33.288 35.269 34.8 37.573 ;
     RECT  4.872 35.317 6.288 35.363 ;
     RECT  25.512 35.797 26.88 36.179 ;
     RECT  27.864 35.797 29.28 36.325 ;
     RECT  24.408 36.133 25.44 37.861 ;
     RECT  25.464 36.179 26.88 37.667 ;
     RECT  31.656 37.093 32.832 38.725 ;
     RECT  28.392 37.139 29.4 38.003 ;
     RECT  25.464 37.667 27.024 39.013 ;
     RECT  33.288 38.675 34.8 39.781 ;
     RECT  25.512 39.013 27.024 42.803 ;
     RECT  31.56 39.203 32.832 40.307 ;
     RECT  33.288 39.781 34.512 41.651 ;
     RECT  6.648 41.221 7.8 43.379 ;
     RECT  24.408 42.227 25.488 43.573 ;
     RECT  6.504 43.379 7.8 44.627 ;
     RECT  35.112 45.253 36.192 47.843 ;
     RECT  17.16 46.645 18.6 47.363 ;
     RECT  33.672 46.931 34.8 47.315 ;
     RECT  33.432 47.315 34.8 47.891 ;
     RECT  29.712 48.083 30.168 49.525 ;
     RECT  20.544 48.275 20.568 49.477 ;
     RECT  18.912 49.477 20.064 49.525 ;
     RECT  20.088 49.477 20.568 49.525 ;
     RECT  18.36 49.703 19.632 51.708 ;
     RECT  18.408 51.708 18.72 51.792 ;
     RECT  18.84 51.708 19.152 51.792 ;
     RECT  19.272 51.708 19.584 51.792 ;
  END
END dsfd_vm_static_read_v1_p
END LIBRARY
